# Generated by FakeRAM 2.0
VERSION 5.7 ;
BUSBITCHARS "[]" ;
PROPERTYDEFINITIONS
  MACRO width INTEGER ;
  MACRO depth INTEGER ;
  MACRO banks INTEGER ;
END PROPERTYDEFINITIONS
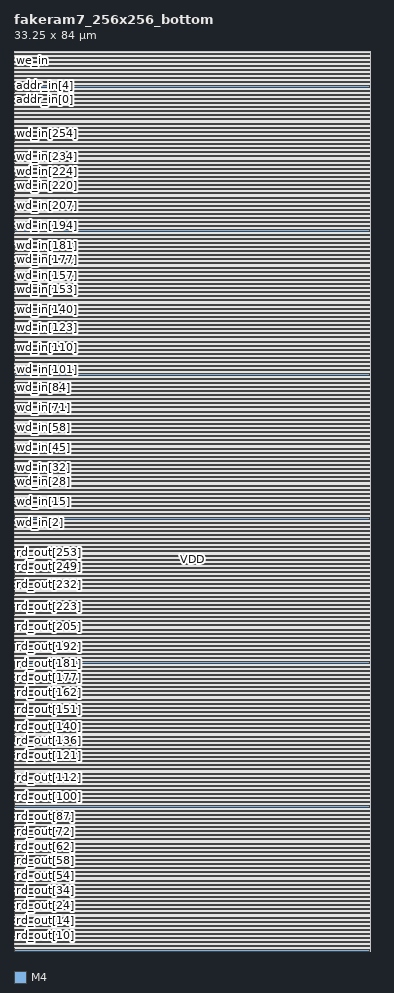
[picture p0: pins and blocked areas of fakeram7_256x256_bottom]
MACRO fakeram7_256x256_bottom
  PROPERTY width 256 ;
  PROPERTY depth 256 ;
  PROPERTY banks 1 ;
  FOREIGN fakeram7_256x256_bottom 0 0 ;
  SYMMETRY X Y R90 ;
  SIZE 33.250 BY 84.000 ;
  CLASS BLOCK ;
  PIN rd_out[0]
    DIRECTION OUTPUT ;
    USE SIGNAL ;
    SHAPE ABUTMENT ;
    PORT
      LAYER M4 ;
      RECT 0.000 0.039 0.024 0.063 ;
    END
  END rd_out[0]
  PIN rd_out[1]
    DIRECTION OUTPUT ;
    USE SIGNAL ;
    SHAPE ABUTMENT ;
    PORT
      LAYER M4 ;
      RECT 0.000 0.183 0.024 0.207 ;
    END
  END rd_out[1]
  PIN rd_out[2]
    DIRECTION OUTPUT ;
    USE SIGNAL ;
    SHAPE ABUTMENT ;
    PORT
      LAYER M4 ;
      RECT 0.000 0.327 0.024 0.351 ;
    END
  END rd_out[2]
  PIN rd_out[3]
    DIRECTION OUTPUT ;
    USE SIGNAL ;
    SHAPE ABUTMENT ;
    PORT
      LAYER M4 ;
      RECT 0.000 0.471 0.024 0.495 ;
    END
  END rd_out[3]
  PIN rd_out[4]
    DIRECTION OUTPUT ;
    USE SIGNAL ;
    SHAPE ABUTMENT ;
    PORT
      LAYER M4 ;
      RECT 0.000 0.615 0.024 0.639 ;
    END
  END rd_out[4]
  PIN rd_out[5]
    DIRECTION OUTPUT ;
    USE SIGNAL ;
    SHAPE ABUTMENT ;
    PORT
      LAYER M4 ;
      RECT 0.000 0.759 0.024 0.783 ;
    END
  END rd_out[5]
  PIN rd_out[6]
    DIRECTION OUTPUT ;
    USE SIGNAL ;
    SHAPE ABUTMENT ;
    PORT
      LAYER M4 ;
      RECT 0.000 0.903 0.024 0.927 ;
    END
  END rd_out[6]
  PIN rd_out[7]
    DIRECTION OUTPUT ;
    USE SIGNAL ;
    SHAPE ABUTMENT ;
    PORT
      LAYER M4 ;
      RECT 0.000 1.047 0.024 1.071 ;
    END
  END rd_out[7]
  PIN rd_out[8]
    DIRECTION OUTPUT ;
    USE SIGNAL ;
    SHAPE ABUTMENT ;
    PORT
      LAYER M4 ;
      RECT 0.000 1.191 0.024 1.215 ;
    END
  END rd_out[8]
  PIN rd_out[9]
    DIRECTION OUTPUT ;
    USE SIGNAL ;
    SHAPE ABUTMENT ;
    PORT
      LAYER M4 ;
      RECT 0.000 1.335 0.024 1.359 ;
    END
  END rd_out[9]
  PIN rd_out[10]
    DIRECTION OUTPUT ;
    USE SIGNAL ;
    SHAPE ABUTMENT ;
    PORT
      LAYER M4 ;
      RECT 0.000 1.479 0.024 1.503 ;
    END
  END rd_out[10]
  PIN rd_out[11]
    DIRECTION OUTPUT ;
    USE SIGNAL ;
    SHAPE ABUTMENT ;
    PORT
      LAYER M4 ;
      RECT 0.000 1.623 0.024 1.647 ;
    END
  END rd_out[11]
  PIN rd_out[12]
    DIRECTION OUTPUT ;
    USE SIGNAL ;
    SHAPE ABUTMENT ;
    PORT
      LAYER M4 ;
      RECT 0.000 1.767 0.024 1.791 ;
    END
  END rd_out[12]
  PIN rd_out[13]
    DIRECTION OUTPUT ;
    USE SIGNAL ;
    SHAPE ABUTMENT ;
    PORT
      LAYER M4 ;
      RECT 0.000 1.911 0.024 1.935 ;
    END
  END rd_out[13]
  PIN rd_out[14]
    DIRECTION OUTPUT ;
    USE SIGNAL ;
    SHAPE ABUTMENT ;
    PORT
      LAYER M4 ;
      RECT 0.000 2.055 0.024 2.079 ;
    END
  END rd_out[14]
  PIN rd_out[15]
    DIRECTION OUTPUT ;
    USE SIGNAL ;
    SHAPE ABUTMENT ;
    PORT
      LAYER M4 ;
      RECT 0.000 2.199 0.024 2.223 ;
    END
  END rd_out[15]
  PIN rd_out[16]
    DIRECTION OUTPUT ;
    USE SIGNAL ;
    SHAPE ABUTMENT ;
    PORT
      LAYER M4 ;
      RECT 0.000 2.343 0.024 2.367 ;
    END
  END rd_out[16]
  PIN rd_out[17]
    DIRECTION OUTPUT ;
    USE SIGNAL ;
    SHAPE ABUTMENT ;
    PORT
      LAYER M4 ;
      RECT 0.000 2.487 0.024 2.511 ;
    END
  END rd_out[17]
  PIN rd_out[18]
    DIRECTION OUTPUT ;
    USE SIGNAL ;
    SHAPE ABUTMENT ;
    PORT
      LAYER M4 ;
      RECT 0.000 2.631 0.024 2.655 ;
    END
  END rd_out[18]
  PIN rd_out[19]
    DIRECTION OUTPUT ;
    USE SIGNAL ;
    SHAPE ABUTMENT ;
    PORT
      LAYER M4 ;
      RECT 0.000 2.775 0.024 2.799 ;
    END
  END rd_out[19]
  PIN rd_out[20]
    DIRECTION OUTPUT ;
    USE SIGNAL ;
    SHAPE ABUTMENT ;
    PORT
      LAYER M4 ;
      RECT 0.000 2.919 0.024 2.943 ;
    END
  END rd_out[20]
  PIN rd_out[21]
    DIRECTION OUTPUT ;
    USE SIGNAL ;
    SHAPE ABUTMENT ;
    PORT
      LAYER M4 ;
      RECT 0.000 3.063 0.024 3.087 ;
    END
  END rd_out[21]
  PIN rd_out[22]
    DIRECTION OUTPUT ;
    USE SIGNAL ;
    SHAPE ABUTMENT ;
    PORT
      LAYER M4 ;
      RECT 0.000 3.207 0.024 3.231 ;
    END
  END rd_out[22]
  PIN rd_out[23]
    DIRECTION OUTPUT ;
    USE SIGNAL ;
    SHAPE ABUTMENT ;
    PORT
      LAYER M4 ;
      RECT 0.000 3.351 0.024 3.375 ;
    END
  END rd_out[23]
  PIN rd_out[24]
    DIRECTION OUTPUT ;
    USE SIGNAL ;
    SHAPE ABUTMENT ;
    PORT
      LAYER M4 ;
      RECT 0.000 3.495 0.024 3.519 ;
    END
  END rd_out[24]
  PIN rd_out[25]
    DIRECTION OUTPUT ;
    USE SIGNAL ;
    SHAPE ABUTMENT ;
    PORT
      LAYER M4 ;
      RECT 0.000 3.639 0.024 3.663 ;
    END
  END rd_out[25]
  PIN rd_out[26]
    DIRECTION OUTPUT ;
    USE SIGNAL ;
    SHAPE ABUTMENT ;
    PORT
      LAYER M4 ;
      RECT 0.000 3.783 0.024 3.807 ;
    END
  END rd_out[26]
  PIN rd_out[27]
    DIRECTION OUTPUT ;
    USE SIGNAL ;
    SHAPE ABUTMENT ;
    PORT
      LAYER M4 ;
      RECT 0.000 3.927 0.024 3.951 ;
    END
  END rd_out[27]
  PIN rd_out[28]
    DIRECTION OUTPUT ;
    USE SIGNAL ;
    SHAPE ABUTMENT ;
    PORT
      LAYER M4 ;
      RECT 0.000 4.071 0.024 4.095 ;
    END
  END rd_out[28]
  PIN rd_out[29]
    DIRECTION OUTPUT ;
    USE SIGNAL ;
    SHAPE ABUTMENT ;
    PORT
      LAYER M4 ;
      RECT 0.000 4.215 0.024 4.239 ;
    END
  END rd_out[29]
  PIN rd_out[30]
    DIRECTION OUTPUT ;
    USE SIGNAL ;
    SHAPE ABUTMENT ;
    PORT
      LAYER M4 ;
      RECT 0.000 4.359 0.024 4.383 ;
    END
  END rd_out[30]
  PIN rd_out[31]
    DIRECTION OUTPUT ;
    USE SIGNAL ;
    SHAPE ABUTMENT ;
    PORT
      LAYER M4 ;
      RECT 0.000 4.503 0.024 4.527 ;
    END
  END rd_out[31]
  PIN rd_out[32]
    DIRECTION OUTPUT ;
    USE SIGNAL ;
    SHAPE ABUTMENT ;
    PORT
      LAYER M4 ;
      RECT 0.000 4.647 0.024 4.671 ;
    END
  END rd_out[32]
  PIN rd_out[33]
    DIRECTION OUTPUT ;
    USE SIGNAL ;
    SHAPE ABUTMENT ;
    PORT
      LAYER M4 ;
      RECT 0.000 4.791 0.024 4.815 ;
    END
  END rd_out[33]
  PIN rd_out[34]
    DIRECTION OUTPUT ;
    USE SIGNAL ;
    SHAPE ABUTMENT ;
    PORT
      LAYER M4 ;
      RECT 0.000 4.935 0.024 4.959 ;
    END
  END rd_out[34]
  PIN rd_out[35]
    DIRECTION OUTPUT ;
    USE SIGNAL ;
    SHAPE ABUTMENT ;
    PORT
      LAYER M4 ;
      RECT 0.000 5.079 0.024 5.103 ;
    END
  END rd_out[35]
  PIN rd_out[36]
    DIRECTION OUTPUT ;
    USE SIGNAL ;
    SHAPE ABUTMENT ;
    PORT
      LAYER M4 ;
      RECT 0.000 5.223 0.024 5.247 ;
    END
  END rd_out[36]
  PIN rd_out[37]
    DIRECTION OUTPUT ;
    USE SIGNAL ;
    SHAPE ABUTMENT ;
    PORT
      LAYER M4 ;
      RECT 0.000 5.367 0.024 5.391 ;
    END
  END rd_out[37]
  PIN rd_out[38]
    DIRECTION OUTPUT ;
    USE SIGNAL ;
    SHAPE ABUTMENT ;
    PORT
      LAYER M4 ;
      RECT 0.000 5.511 0.024 5.535 ;
    END
  END rd_out[38]
  PIN rd_out[39]
    DIRECTION OUTPUT ;
    USE SIGNAL ;
    SHAPE ABUTMENT ;
    PORT
      LAYER M4 ;
      RECT 0.000 5.655 0.024 5.679 ;
    END
  END rd_out[39]
  PIN rd_out[40]
    DIRECTION OUTPUT ;
    USE SIGNAL ;
    SHAPE ABUTMENT ;
    PORT
      LAYER M4 ;
      RECT 0.000 5.799 0.024 5.823 ;
    END
  END rd_out[40]
  PIN rd_out[41]
    DIRECTION OUTPUT ;
    USE SIGNAL ;
    SHAPE ABUTMENT ;
    PORT
      LAYER M4 ;
      RECT 0.000 5.943 0.024 5.967 ;
    END
  END rd_out[41]
  PIN rd_out[42]
    DIRECTION OUTPUT ;
    USE SIGNAL ;
    SHAPE ABUTMENT ;
    PORT
      LAYER M4 ;
      RECT 0.000 6.087 0.024 6.111 ;
    END
  END rd_out[42]
  PIN rd_out[43]
    DIRECTION OUTPUT ;
    USE SIGNAL ;
    SHAPE ABUTMENT ;
    PORT
      LAYER M4 ;
      RECT 0.000 6.231 0.024 6.255 ;
    END
  END rd_out[43]
  PIN rd_out[44]
    DIRECTION OUTPUT ;
    USE SIGNAL ;
    SHAPE ABUTMENT ;
    PORT
      LAYER M4 ;
      RECT 0.000 6.375 0.024 6.399 ;
    END
  END rd_out[44]
  PIN rd_out[45]
    DIRECTION OUTPUT ;
    USE SIGNAL ;
    SHAPE ABUTMENT ;
    PORT
      LAYER M4 ;
      RECT 0.000 6.519 0.024 6.543 ;
    END
  END rd_out[45]
  PIN rd_out[46]
    DIRECTION OUTPUT ;
    USE SIGNAL ;
    SHAPE ABUTMENT ;
    PORT
      LAYER M4 ;
      RECT 0.000 6.663 0.024 6.687 ;
    END
  END rd_out[46]
  PIN rd_out[47]
    DIRECTION OUTPUT ;
    USE SIGNAL ;
    SHAPE ABUTMENT ;
    PORT
      LAYER M4 ;
      RECT 0.000 6.807 0.024 6.831 ;
    END
  END rd_out[47]
  PIN rd_out[48]
    DIRECTION OUTPUT ;
    USE SIGNAL ;
    SHAPE ABUTMENT ;
    PORT
      LAYER M4 ;
      RECT 0.000 6.951 0.024 6.975 ;
    END
  END rd_out[48]
  PIN rd_out[49]
    DIRECTION OUTPUT ;
    USE SIGNAL ;
    SHAPE ABUTMENT ;
    PORT
      LAYER M4 ;
      RECT 0.000 7.095 0.024 7.119 ;
    END
  END rd_out[49]
  PIN rd_out[50]
    DIRECTION OUTPUT ;
    USE SIGNAL ;
    SHAPE ABUTMENT ;
    PORT
      LAYER M4 ;
      RECT 0.000 7.239 0.024 7.263 ;
    END
  END rd_out[50]
  PIN rd_out[51]
    DIRECTION OUTPUT ;
    USE SIGNAL ;
    SHAPE ABUTMENT ;
    PORT
      LAYER M4 ;
      RECT 0.000 7.383 0.024 7.407 ;
    END
  END rd_out[51]
  PIN rd_out[52]
    DIRECTION OUTPUT ;
    USE SIGNAL ;
    SHAPE ABUTMENT ;
    PORT
      LAYER M4 ;
      RECT 0.000 7.527 0.024 7.551 ;
    END
  END rd_out[52]
  PIN rd_out[53]
    DIRECTION OUTPUT ;
    USE SIGNAL ;
    SHAPE ABUTMENT ;
    PORT
      LAYER M4 ;
      RECT 0.000 7.671 0.024 7.695 ;
    END
  END rd_out[53]
  PIN rd_out[54]
    DIRECTION OUTPUT ;
    USE SIGNAL ;
    SHAPE ABUTMENT ;
    PORT
      LAYER M4 ;
      RECT 0.000 7.815 0.024 7.839 ;
    END
  END rd_out[54]
  PIN rd_out[55]
    DIRECTION OUTPUT ;
    USE SIGNAL ;
    SHAPE ABUTMENT ;
    PORT
      LAYER M4 ;
      RECT 0.000 7.959 0.024 7.983 ;
    END
  END rd_out[55]
  PIN rd_out[56]
    DIRECTION OUTPUT ;
    USE SIGNAL ;
    SHAPE ABUTMENT ;
    PORT
      LAYER M4 ;
      RECT 0.000 8.103 0.024 8.127 ;
    END
  END rd_out[56]
  PIN rd_out[57]
    DIRECTION OUTPUT ;
    USE SIGNAL ;
    SHAPE ABUTMENT ;
    PORT
      LAYER M4 ;
      RECT 0.000 8.247 0.024 8.271 ;
    END
  END rd_out[57]
  PIN rd_out[58]
    DIRECTION OUTPUT ;
    USE SIGNAL ;
    SHAPE ABUTMENT ;
    PORT
      LAYER M4 ;
      RECT 0.000 8.391 0.024 8.415 ;
    END
  END rd_out[58]
  PIN rd_out[59]
    DIRECTION OUTPUT ;
    USE SIGNAL ;
    SHAPE ABUTMENT ;
    PORT
      LAYER M4 ;
      RECT 0.000 8.535 0.024 8.559 ;
    END
  END rd_out[59]
  PIN rd_out[60]
    DIRECTION OUTPUT ;
    USE SIGNAL ;
    SHAPE ABUTMENT ;
    PORT
      LAYER M4 ;
      RECT 0.000 8.679 0.024 8.703 ;
    END
  END rd_out[60]
  PIN rd_out[61]
    DIRECTION OUTPUT ;
    USE SIGNAL ;
    SHAPE ABUTMENT ;
    PORT
      LAYER M4 ;
      RECT 0.000 8.823 0.024 8.847 ;
    END
  END rd_out[61]
  PIN rd_out[62]
    DIRECTION OUTPUT ;
    USE SIGNAL ;
    SHAPE ABUTMENT ;
    PORT
      LAYER M4 ;
      RECT 0.000 8.967 0.024 8.991 ;
    END
  END rd_out[62]
  PIN rd_out[63]
    DIRECTION OUTPUT ;
    USE SIGNAL ;
    SHAPE ABUTMENT ;
    PORT
      LAYER M4 ;
      RECT 0.000 9.111 0.024 9.135 ;
    END
  END rd_out[63]
  PIN rd_out[64]
    DIRECTION OUTPUT ;
    USE SIGNAL ;
    SHAPE ABUTMENT ;
    PORT
      LAYER M4 ;
      RECT 0.000 9.255 0.024 9.279 ;
    END
  END rd_out[64]
  PIN rd_out[65]
    DIRECTION OUTPUT ;
    USE SIGNAL ;
    SHAPE ABUTMENT ;
    PORT
      LAYER M4 ;
      RECT 0.000 9.399 0.024 9.423 ;
    END
  END rd_out[65]
  PIN rd_out[66]
    DIRECTION OUTPUT ;
    USE SIGNAL ;
    SHAPE ABUTMENT ;
    PORT
      LAYER M4 ;
      RECT 0.000 9.543 0.024 9.567 ;
    END
  END rd_out[66]
  PIN rd_out[67]
    DIRECTION OUTPUT ;
    USE SIGNAL ;
    SHAPE ABUTMENT ;
    PORT
      LAYER M4 ;
      RECT 0.000 9.687 0.024 9.711 ;
    END
  END rd_out[67]
  PIN rd_out[68]
    DIRECTION OUTPUT ;
    USE SIGNAL ;
    SHAPE ABUTMENT ;
    PORT
      LAYER M4 ;
      RECT 0.000 9.831 0.024 9.855 ;
    END
  END rd_out[68]
  PIN rd_out[69]
    DIRECTION OUTPUT ;
    USE SIGNAL ;
    SHAPE ABUTMENT ;
    PORT
      LAYER M4 ;
      RECT 0.000 9.975 0.024 9.999 ;
    END
  END rd_out[69]
  PIN rd_out[70]
    DIRECTION OUTPUT ;
    USE SIGNAL ;
    SHAPE ABUTMENT ;
    PORT
      LAYER M4 ;
      RECT 0.000 10.119 0.024 10.143 ;
    END
  END rd_out[70]
  PIN rd_out[71]
    DIRECTION OUTPUT ;
    USE SIGNAL ;
    SHAPE ABUTMENT ;
    PORT
      LAYER M4 ;
      RECT 0.000 10.263 0.024 10.287 ;
    END
  END rd_out[71]
  PIN rd_out[72]
    DIRECTION OUTPUT ;
    USE SIGNAL ;
    SHAPE ABUTMENT ;
    PORT
      LAYER M4 ;
      RECT 0.000 10.407 0.024 10.431 ;
    END
  END rd_out[72]
  PIN rd_out[73]
    DIRECTION OUTPUT ;
    USE SIGNAL ;
    SHAPE ABUTMENT ;
    PORT
      LAYER M4 ;
      RECT 0.000 10.551 0.024 10.575 ;
    END
  END rd_out[73]
  PIN rd_out[74]
    DIRECTION OUTPUT ;
    USE SIGNAL ;
    SHAPE ABUTMENT ;
    PORT
      LAYER M4 ;
      RECT 0.000 10.695 0.024 10.719 ;
    END
  END rd_out[74]
  PIN rd_out[75]
    DIRECTION OUTPUT ;
    USE SIGNAL ;
    SHAPE ABUTMENT ;
    PORT
      LAYER M4 ;
      RECT 0.000 10.839 0.024 10.863 ;
    END
  END rd_out[75]
  PIN rd_out[76]
    DIRECTION OUTPUT ;
    USE SIGNAL ;
    SHAPE ABUTMENT ;
    PORT
      LAYER M4 ;
      RECT 0.000 10.983 0.024 11.007 ;
    END
  END rd_out[76]
  PIN rd_out[77]
    DIRECTION OUTPUT ;
    USE SIGNAL ;
    SHAPE ABUTMENT ;
    PORT
      LAYER M4 ;
      RECT 0.000 11.127 0.024 11.151 ;
    END
  END rd_out[77]
  PIN rd_out[78]
    DIRECTION OUTPUT ;
    USE SIGNAL ;
    SHAPE ABUTMENT ;
    PORT
      LAYER M4 ;
      RECT 0.000 11.271 0.024 11.295 ;
    END
  END rd_out[78]
  PIN rd_out[79]
    DIRECTION OUTPUT ;
    USE SIGNAL ;
    SHAPE ABUTMENT ;
    PORT
      LAYER M4 ;
      RECT 0.000 11.415 0.024 11.439 ;
    END
  END rd_out[79]
  PIN rd_out[80]
    DIRECTION OUTPUT ;
    USE SIGNAL ;
    SHAPE ABUTMENT ;
    PORT
      LAYER M4 ;
      RECT 0.000 11.559 0.024 11.583 ;
    END
  END rd_out[80]
  PIN rd_out[81]
    DIRECTION OUTPUT ;
    USE SIGNAL ;
    SHAPE ABUTMENT ;
    PORT
      LAYER M4 ;
      RECT 0.000 11.703 0.024 11.727 ;
    END
  END rd_out[81]
  PIN rd_out[82]
    DIRECTION OUTPUT ;
    USE SIGNAL ;
    SHAPE ABUTMENT ;
    PORT
      LAYER M4 ;
      RECT 0.000 11.847 0.024 11.871 ;
    END
  END rd_out[82]
  PIN rd_out[83]
    DIRECTION OUTPUT ;
    USE SIGNAL ;
    SHAPE ABUTMENT ;
    PORT
      LAYER M4 ;
      RECT 0.000 11.991 0.024 12.015 ;
    END
  END rd_out[83]
  PIN rd_out[84]
    DIRECTION OUTPUT ;
    USE SIGNAL ;
    SHAPE ABUTMENT ;
    PORT
      LAYER M4 ;
      RECT 0.000 12.135 0.024 12.159 ;
    END
  END rd_out[84]
  PIN rd_out[85]
    DIRECTION OUTPUT ;
    USE SIGNAL ;
    SHAPE ABUTMENT ;
    PORT
      LAYER M4 ;
      RECT 0.000 12.279 0.024 12.303 ;
    END
  END rd_out[85]
  PIN rd_out[86]
    DIRECTION OUTPUT ;
    USE SIGNAL ;
    SHAPE ABUTMENT ;
    PORT
      LAYER M4 ;
      RECT 0.000 12.423 0.024 12.447 ;
    END
  END rd_out[86]
  PIN rd_out[87]
    DIRECTION OUTPUT ;
    USE SIGNAL ;
    SHAPE ABUTMENT ;
    PORT
      LAYER M4 ;
      RECT 0.000 12.567 0.024 12.591 ;
    END
  END rd_out[87]
  PIN rd_out[88]
    DIRECTION OUTPUT ;
    USE SIGNAL ;
    SHAPE ABUTMENT ;
    PORT
      LAYER M4 ;
      RECT 0.000 12.711 0.024 12.735 ;
    END
  END rd_out[88]
  PIN rd_out[89]
    DIRECTION OUTPUT ;
    USE SIGNAL ;
    SHAPE ABUTMENT ;
    PORT
      LAYER M4 ;
      RECT 0.000 12.855 0.024 12.879 ;
    END
  END rd_out[89]
  PIN rd_out[90]
    DIRECTION OUTPUT ;
    USE SIGNAL ;
    SHAPE ABUTMENT ;
    PORT
      LAYER M4 ;
      RECT 0.000 12.999 0.024 13.023 ;
    END
  END rd_out[90]
  PIN rd_out[91]
    DIRECTION OUTPUT ;
    USE SIGNAL ;
    SHAPE ABUTMENT ;
    PORT
      LAYER M4 ;
      RECT 0.000 13.143 0.024 13.167 ;
    END
  END rd_out[91]
  PIN rd_out[92]
    DIRECTION OUTPUT ;
    USE SIGNAL ;
    SHAPE ABUTMENT ;
    PORT
      LAYER M4 ;
      RECT 0.000 13.287 0.024 13.311 ;
    END
  END rd_out[92]
  PIN rd_out[93]
    DIRECTION OUTPUT ;
    USE SIGNAL ;
    SHAPE ABUTMENT ;
    PORT
      LAYER M4 ;
      RECT 0.000 13.431 0.024 13.455 ;
    END
  END rd_out[93]
  PIN rd_out[94]
    DIRECTION OUTPUT ;
    USE SIGNAL ;
    SHAPE ABUTMENT ;
    PORT
      LAYER M4 ;
      RECT 0.000 13.575 0.024 13.599 ;
    END
  END rd_out[94]
  PIN rd_out[95]
    DIRECTION OUTPUT ;
    USE SIGNAL ;
    SHAPE ABUTMENT ;
    PORT
      LAYER M4 ;
      RECT 0.000 13.719 0.024 13.743 ;
    END
  END rd_out[95]
  PIN rd_out[96]
    DIRECTION OUTPUT ;
    USE SIGNAL ;
    SHAPE ABUTMENT ;
    PORT
      LAYER M4 ;
      RECT 0.000 13.863 0.024 13.887 ;
    END
  END rd_out[96]
  PIN rd_out[97]
    DIRECTION OUTPUT ;
    USE SIGNAL ;
    SHAPE ABUTMENT ;
    PORT
      LAYER M4 ;
      RECT 0.000 14.007 0.024 14.031 ;
    END
  END rd_out[97]
  PIN rd_out[98]
    DIRECTION OUTPUT ;
    USE SIGNAL ;
    SHAPE ABUTMENT ;
    PORT
      LAYER M4 ;
      RECT 0.000 14.151 0.024 14.175 ;
    END
  END rd_out[98]
  PIN rd_out[99]
    DIRECTION OUTPUT ;
    USE SIGNAL ;
    SHAPE ABUTMENT ;
    PORT
      LAYER M4 ;
      RECT 0.000 14.295 0.024 14.319 ;
    END
  END rd_out[99]
  PIN rd_out[100]
    DIRECTION OUTPUT ;
    USE SIGNAL ;
    SHAPE ABUTMENT ;
    PORT
      LAYER M4 ;
      RECT 0.000 14.439 0.024 14.463 ;
    END
  END rd_out[100]
  PIN rd_out[101]
    DIRECTION OUTPUT ;
    USE SIGNAL ;
    SHAPE ABUTMENT ;
    PORT
      LAYER M4 ;
      RECT 0.000 14.583 0.024 14.607 ;
    END
  END rd_out[101]
  PIN rd_out[102]
    DIRECTION OUTPUT ;
    USE SIGNAL ;
    SHAPE ABUTMENT ;
    PORT
      LAYER M4 ;
      RECT 0.000 14.727 0.024 14.751 ;
    END
  END rd_out[102]
  PIN rd_out[103]
    DIRECTION OUTPUT ;
    USE SIGNAL ;
    SHAPE ABUTMENT ;
    PORT
      LAYER M4 ;
      RECT 0.000 14.871 0.024 14.895 ;
    END
  END rd_out[103]
  PIN rd_out[104]
    DIRECTION OUTPUT ;
    USE SIGNAL ;
    SHAPE ABUTMENT ;
    PORT
      LAYER M4 ;
      RECT 0.000 15.015 0.024 15.039 ;
    END
  END rd_out[104]
  PIN rd_out[105]
    DIRECTION OUTPUT ;
    USE SIGNAL ;
    SHAPE ABUTMENT ;
    PORT
      LAYER M4 ;
      RECT 0.000 15.159 0.024 15.183 ;
    END
  END rd_out[105]
  PIN rd_out[106]
    DIRECTION OUTPUT ;
    USE SIGNAL ;
    SHAPE ABUTMENT ;
    PORT
      LAYER M4 ;
      RECT 0.000 15.303 0.024 15.327 ;
    END
  END rd_out[106]
  PIN rd_out[107]
    DIRECTION OUTPUT ;
    USE SIGNAL ;
    SHAPE ABUTMENT ;
    PORT
      LAYER M4 ;
      RECT 0.000 15.447 0.024 15.471 ;
    END
  END rd_out[107]
  PIN rd_out[108]
    DIRECTION OUTPUT ;
    USE SIGNAL ;
    SHAPE ABUTMENT ;
    PORT
      LAYER M4 ;
      RECT 0.000 15.591 0.024 15.615 ;
    END
  END rd_out[108]
  PIN rd_out[109]
    DIRECTION OUTPUT ;
    USE SIGNAL ;
    SHAPE ABUTMENT ;
    PORT
      LAYER M4 ;
      RECT 0.000 15.735 0.024 15.759 ;
    END
  END rd_out[109]
  PIN rd_out[110]
    DIRECTION OUTPUT ;
    USE SIGNAL ;
    SHAPE ABUTMENT ;
    PORT
      LAYER M4 ;
      RECT 0.000 15.879 0.024 15.903 ;
    END
  END rd_out[110]
  PIN rd_out[111]
    DIRECTION OUTPUT ;
    USE SIGNAL ;
    SHAPE ABUTMENT ;
    PORT
      LAYER M4 ;
      RECT 0.000 16.023 0.024 16.047 ;
    END
  END rd_out[111]
  PIN rd_out[112]
    DIRECTION OUTPUT ;
    USE SIGNAL ;
    SHAPE ABUTMENT ;
    PORT
      LAYER M4 ;
      RECT 0.000 16.167 0.024 16.191 ;
    END
  END rd_out[112]
  PIN rd_out[113]
    DIRECTION OUTPUT ;
    USE SIGNAL ;
    SHAPE ABUTMENT ;
    PORT
      LAYER M4 ;
      RECT 0.000 16.311 0.024 16.335 ;
    END
  END rd_out[113]
  PIN rd_out[114]
    DIRECTION OUTPUT ;
    USE SIGNAL ;
    SHAPE ABUTMENT ;
    PORT
      LAYER M4 ;
      RECT 0.000 16.455 0.024 16.479 ;
    END
  END rd_out[114]
  PIN rd_out[115]
    DIRECTION OUTPUT ;
    USE SIGNAL ;
    SHAPE ABUTMENT ;
    PORT
      LAYER M4 ;
      RECT 0.000 16.599 0.024 16.623 ;
    END
  END rd_out[115]
  PIN rd_out[116]
    DIRECTION OUTPUT ;
    USE SIGNAL ;
    SHAPE ABUTMENT ;
    PORT
      LAYER M4 ;
      RECT 0.000 16.743 0.024 16.767 ;
    END
  END rd_out[116]
  PIN rd_out[117]
    DIRECTION OUTPUT ;
    USE SIGNAL ;
    SHAPE ABUTMENT ;
    PORT
      LAYER M4 ;
      RECT 0.000 16.887 0.024 16.911 ;
    END
  END rd_out[117]
  PIN rd_out[118]
    DIRECTION OUTPUT ;
    USE SIGNAL ;
    SHAPE ABUTMENT ;
    PORT
      LAYER M4 ;
      RECT 0.000 17.031 0.024 17.055 ;
    END
  END rd_out[118]
  PIN rd_out[119]
    DIRECTION OUTPUT ;
    USE SIGNAL ;
    SHAPE ABUTMENT ;
    PORT
      LAYER M4 ;
      RECT 0.000 17.175 0.024 17.199 ;
    END
  END rd_out[119]
  PIN rd_out[120]
    DIRECTION OUTPUT ;
    USE SIGNAL ;
    SHAPE ABUTMENT ;
    PORT
      LAYER M4 ;
      RECT 0.000 17.319 0.024 17.343 ;
    END
  END rd_out[120]
  PIN rd_out[121]
    DIRECTION OUTPUT ;
    USE SIGNAL ;
    SHAPE ABUTMENT ;
    PORT
      LAYER M4 ;
      RECT 0.000 17.463 0.024 17.487 ;
    END
  END rd_out[121]
  PIN rd_out[122]
    DIRECTION OUTPUT ;
    USE SIGNAL ;
    SHAPE ABUTMENT ;
    PORT
      LAYER M4 ;
      RECT 0.000 17.607 0.024 17.631 ;
    END
  END rd_out[122]
  PIN rd_out[123]
    DIRECTION OUTPUT ;
    USE SIGNAL ;
    SHAPE ABUTMENT ;
    PORT
      LAYER M4 ;
      RECT 0.000 17.751 0.024 17.775 ;
    END
  END rd_out[123]
  PIN rd_out[124]
    DIRECTION OUTPUT ;
    USE SIGNAL ;
    SHAPE ABUTMENT ;
    PORT
      LAYER M4 ;
      RECT 0.000 17.895 0.024 17.919 ;
    END
  END rd_out[124]
  PIN rd_out[125]
    DIRECTION OUTPUT ;
    USE SIGNAL ;
    SHAPE ABUTMENT ;
    PORT
      LAYER M4 ;
      RECT 0.000 18.039 0.024 18.063 ;
    END
  END rd_out[125]
  PIN rd_out[126]
    DIRECTION OUTPUT ;
    USE SIGNAL ;
    SHAPE ABUTMENT ;
    PORT
      LAYER M4 ;
      RECT 0.000 18.183 0.024 18.207 ;
    END
  END rd_out[126]
  PIN rd_out[127]
    DIRECTION OUTPUT ;
    USE SIGNAL ;
    SHAPE ABUTMENT ;
    PORT
      LAYER M4 ;
      RECT 0.000 18.327 0.024 18.351 ;
    END
  END rd_out[127]
  PIN rd_out[128]
    DIRECTION OUTPUT ;
    USE SIGNAL ;
    SHAPE ABUTMENT ;
    PORT
      LAYER M4 ;
      RECT 0.000 18.471 0.024 18.495 ;
    END
  END rd_out[128]
  PIN rd_out[129]
    DIRECTION OUTPUT ;
    USE SIGNAL ;
    SHAPE ABUTMENT ;
    PORT
      LAYER M4 ;
      RECT 0.000 18.615 0.024 18.639 ;
    END
  END rd_out[129]
  PIN rd_out[130]
    DIRECTION OUTPUT ;
    USE SIGNAL ;
    SHAPE ABUTMENT ;
    PORT
      LAYER M4 ;
      RECT 0.000 18.759 0.024 18.783 ;
    END
  END rd_out[130]
  PIN rd_out[131]
    DIRECTION OUTPUT ;
    USE SIGNAL ;
    SHAPE ABUTMENT ;
    PORT
      LAYER M4 ;
      RECT 0.000 18.903 0.024 18.927 ;
    END
  END rd_out[131]
  PIN rd_out[132]
    DIRECTION OUTPUT ;
    USE SIGNAL ;
    SHAPE ABUTMENT ;
    PORT
      LAYER M4 ;
      RECT 0.000 19.047 0.024 19.071 ;
    END
  END rd_out[132]
  PIN rd_out[133]
    DIRECTION OUTPUT ;
    USE SIGNAL ;
    SHAPE ABUTMENT ;
    PORT
      LAYER M4 ;
      RECT 0.000 19.191 0.024 19.215 ;
    END
  END rd_out[133]
  PIN rd_out[134]
    DIRECTION OUTPUT ;
    USE SIGNAL ;
    SHAPE ABUTMENT ;
    PORT
      LAYER M4 ;
      RECT 0.000 19.335 0.024 19.359 ;
    END
  END rd_out[134]
  PIN rd_out[135]
    DIRECTION OUTPUT ;
    USE SIGNAL ;
    SHAPE ABUTMENT ;
    PORT
      LAYER M4 ;
      RECT 0.000 19.479 0.024 19.503 ;
    END
  END rd_out[135]
  PIN rd_out[136]
    DIRECTION OUTPUT ;
    USE SIGNAL ;
    SHAPE ABUTMENT ;
    PORT
      LAYER M4 ;
      RECT 0.000 19.623 0.024 19.647 ;
    END
  END rd_out[136]
  PIN rd_out[137]
    DIRECTION OUTPUT ;
    USE SIGNAL ;
    SHAPE ABUTMENT ;
    PORT
      LAYER M4 ;
      RECT 0.000 19.767 0.024 19.791 ;
    END
  END rd_out[137]
  PIN rd_out[138]
    DIRECTION OUTPUT ;
    USE SIGNAL ;
    SHAPE ABUTMENT ;
    PORT
      LAYER M4 ;
      RECT 0.000 19.911 0.024 19.935 ;
    END
  END rd_out[138]
  PIN rd_out[139]
    DIRECTION OUTPUT ;
    USE SIGNAL ;
    SHAPE ABUTMENT ;
    PORT
      LAYER M4 ;
      RECT 0.000 20.055 0.024 20.079 ;
    END
  END rd_out[139]
  PIN rd_out[140]
    DIRECTION OUTPUT ;
    USE SIGNAL ;
    SHAPE ABUTMENT ;
    PORT
      LAYER M4 ;
      RECT 0.000 20.199 0.024 20.223 ;
    END
  END rd_out[140]
  PIN rd_out[141]
    DIRECTION OUTPUT ;
    USE SIGNAL ;
    SHAPE ABUTMENT ;
    PORT
      LAYER M4 ;
      RECT 0.000 20.343 0.024 20.367 ;
    END
  END rd_out[141]
  PIN rd_out[142]
    DIRECTION OUTPUT ;
    USE SIGNAL ;
    SHAPE ABUTMENT ;
    PORT
      LAYER M4 ;
      RECT 0.000 20.487 0.024 20.511 ;
    END
  END rd_out[142]
  PIN rd_out[143]
    DIRECTION OUTPUT ;
    USE SIGNAL ;
    SHAPE ABUTMENT ;
    PORT
      LAYER M4 ;
      RECT 0.000 20.631 0.024 20.655 ;
    END
  END rd_out[143]
  PIN rd_out[144]
    DIRECTION OUTPUT ;
    USE SIGNAL ;
    SHAPE ABUTMENT ;
    PORT
      LAYER M4 ;
      RECT 0.000 20.775 0.024 20.799 ;
    END
  END rd_out[144]
  PIN rd_out[145]
    DIRECTION OUTPUT ;
    USE SIGNAL ;
    SHAPE ABUTMENT ;
    PORT
      LAYER M4 ;
      RECT 0.000 20.919 0.024 20.943 ;
    END
  END rd_out[145]
  PIN rd_out[146]
    DIRECTION OUTPUT ;
    USE SIGNAL ;
    SHAPE ABUTMENT ;
    PORT
      LAYER M4 ;
      RECT 0.000 21.063 0.024 21.087 ;
    END
  END rd_out[146]
  PIN rd_out[147]
    DIRECTION OUTPUT ;
    USE SIGNAL ;
    SHAPE ABUTMENT ;
    PORT
      LAYER M4 ;
      RECT 0.000 21.207 0.024 21.231 ;
    END
  END rd_out[147]
  PIN rd_out[148]
    DIRECTION OUTPUT ;
    USE SIGNAL ;
    SHAPE ABUTMENT ;
    PORT
      LAYER M4 ;
      RECT 0.000 21.351 0.024 21.375 ;
    END
  END rd_out[148]
  PIN rd_out[149]
    DIRECTION OUTPUT ;
    USE SIGNAL ;
    SHAPE ABUTMENT ;
    PORT
      LAYER M4 ;
      RECT 0.000 21.495 0.024 21.519 ;
    END
  END rd_out[149]
  PIN rd_out[150]
    DIRECTION OUTPUT ;
    USE SIGNAL ;
    SHAPE ABUTMENT ;
    PORT
      LAYER M4 ;
      RECT 0.000 21.639 0.024 21.663 ;
    END
  END rd_out[150]
  PIN rd_out[151]
    DIRECTION OUTPUT ;
    USE SIGNAL ;
    SHAPE ABUTMENT ;
    PORT
      LAYER M4 ;
      RECT 0.000 21.783 0.024 21.807 ;
    END
  END rd_out[151]
  PIN rd_out[152]
    DIRECTION OUTPUT ;
    USE SIGNAL ;
    SHAPE ABUTMENT ;
    PORT
      LAYER M4 ;
      RECT 0.000 21.927 0.024 21.951 ;
    END
  END rd_out[152]
  PIN rd_out[153]
    DIRECTION OUTPUT ;
    USE SIGNAL ;
    SHAPE ABUTMENT ;
    PORT
      LAYER M4 ;
      RECT 0.000 22.071 0.024 22.095 ;
    END
  END rd_out[153]
  PIN rd_out[154]
    DIRECTION OUTPUT ;
    USE SIGNAL ;
    SHAPE ABUTMENT ;
    PORT
      LAYER M4 ;
      RECT 0.000 22.215 0.024 22.239 ;
    END
  END rd_out[154]
  PIN rd_out[155]
    DIRECTION OUTPUT ;
    USE SIGNAL ;
    SHAPE ABUTMENT ;
    PORT
      LAYER M4 ;
      RECT 0.000 22.359 0.024 22.383 ;
    END
  END rd_out[155]
  PIN rd_out[156]
    DIRECTION OUTPUT ;
    USE SIGNAL ;
    SHAPE ABUTMENT ;
    PORT
      LAYER M4 ;
      RECT 0.000 22.503 0.024 22.527 ;
    END
  END rd_out[156]
  PIN rd_out[157]
    DIRECTION OUTPUT ;
    USE SIGNAL ;
    SHAPE ABUTMENT ;
    PORT
      LAYER M4 ;
      RECT 0.000 22.647 0.024 22.671 ;
    END
  END rd_out[157]
  PIN rd_out[158]
    DIRECTION OUTPUT ;
    USE SIGNAL ;
    SHAPE ABUTMENT ;
    PORT
      LAYER M4 ;
      RECT 0.000 22.791 0.024 22.815 ;
    END
  END rd_out[158]
  PIN rd_out[159]
    DIRECTION OUTPUT ;
    USE SIGNAL ;
    SHAPE ABUTMENT ;
    PORT
      LAYER M4 ;
      RECT 0.000 22.935 0.024 22.959 ;
    END
  END rd_out[159]
  PIN rd_out[160]
    DIRECTION OUTPUT ;
    USE SIGNAL ;
    SHAPE ABUTMENT ;
    PORT
      LAYER M4 ;
      RECT 0.000 23.079 0.024 23.103 ;
    END
  END rd_out[160]
  PIN rd_out[161]
    DIRECTION OUTPUT ;
    USE SIGNAL ;
    SHAPE ABUTMENT ;
    PORT
      LAYER M4 ;
      RECT 0.000 23.223 0.024 23.247 ;
    END
  END rd_out[161]
  PIN rd_out[162]
    DIRECTION OUTPUT ;
    USE SIGNAL ;
    SHAPE ABUTMENT ;
    PORT
      LAYER M4 ;
      RECT 0.000 23.367 0.024 23.391 ;
    END
  END rd_out[162]
  PIN rd_out[163]
    DIRECTION OUTPUT ;
    USE SIGNAL ;
    SHAPE ABUTMENT ;
    PORT
      LAYER M4 ;
      RECT 0.000 23.511 0.024 23.535 ;
    END
  END rd_out[163]
  PIN rd_out[164]
    DIRECTION OUTPUT ;
    USE SIGNAL ;
    SHAPE ABUTMENT ;
    PORT
      LAYER M4 ;
      RECT 0.000 23.655 0.024 23.679 ;
    END
  END rd_out[164]
  PIN rd_out[165]
    DIRECTION OUTPUT ;
    USE SIGNAL ;
    SHAPE ABUTMENT ;
    PORT
      LAYER M4 ;
      RECT 0.000 23.799 0.024 23.823 ;
    END
  END rd_out[165]
  PIN rd_out[166]
    DIRECTION OUTPUT ;
    USE SIGNAL ;
    SHAPE ABUTMENT ;
    PORT
      LAYER M4 ;
      RECT 0.000 23.943 0.024 23.967 ;
    END
  END rd_out[166]
  PIN rd_out[167]
    DIRECTION OUTPUT ;
    USE SIGNAL ;
    SHAPE ABUTMENT ;
    PORT
      LAYER M4 ;
      RECT 0.000 24.087 0.024 24.111 ;
    END
  END rd_out[167]
  PIN rd_out[168]
    DIRECTION OUTPUT ;
    USE SIGNAL ;
    SHAPE ABUTMENT ;
    PORT
      LAYER M4 ;
      RECT 0.000 24.231 0.024 24.255 ;
    END
  END rd_out[168]
  PIN rd_out[169]
    DIRECTION OUTPUT ;
    USE SIGNAL ;
    SHAPE ABUTMENT ;
    PORT
      LAYER M4 ;
      RECT 0.000 24.375 0.024 24.399 ;
    END
  END rd_out[169]
  PIN rd_out[170]
    DIRECTION OUTPUT ;
    USE SIGNAL ;
    SHAPE ABUTMENT ;
    PORT
      LAYER M4 ;
      RECT 0.000 24.519 0.024 24.543 ;
    END
  END rd_out[170]
  PIN rd_out[171]
    DIRECTION OUTPUT ;
    USE SIGNAL ;
    SHAPE ABUTMENT ;
    PORT
      LAYER M4 ;
      RECT 0.000 24.663 0.024 24.687 ;
    END
  END rd_out[171]
  PIN rd_out[172]
    DIRECTION OUTPUT ;
    USE SIGNAL ;
    SHAPE ABUTMENT ;
    PORT
      LAYER M4 ;
      RECT 0.000 24.807 0.024 24.831 ;
    END
  END rd_out[172]
  PIN rd_out[173]
    DIRECTION OUTPUT ;
    USE SIGNAL ;
    SHAPE ABUTMENT ;
    PORT
      LAYER M4 ;
      RECT 0.000 24.951 0.024 24.975 ;
    END
  END rd_out[173]
  PIN rd_out[174]
    DIRECTION OUTPUT ;
    USE SIGNAL ;
    SHAPE ABUTMENT ;
    PORT
      LAYER M4 ;
      RECT 0.000 25.095 0.024 25.119 ;
    END
  END rd_out[174]
  PIN rd_out[175]
    DIRECTION OUTPUT ;
    USE SIGNAL ;
    SHAPE ABUTMENT ;
    PORT
      LAYER M4 ;
      RECT 0.000 25.239 0.024 25.263 ;
    END
  END rd_out[175]
  PIN rd_out[176]
    DIRECTION OUTPUT ;
    USE SIGNAL ;
    SHAPE ABUTMENT ;
    PORT
      LAYER M4 ;
      RECT 0.000 25.383 0.024 25.407 ;
    END
  END rd_out[176]
  PIN rd_out[177]
    DIRECTION OUTPUT ;
    USE SIGNAL ;
    SHAPE ABUTMENT ;
    PORT
      LAYER M4 ;
      RECT 0.000 25.527 0.024 25.551 ;
    END
  END rd_out[177]
  PIN rd_out[178]
    DIRECTION OUTPUT ;
    USE SIGNAL ;
    SHAPE ABUTMENT ;
    PORT
      LAYER M4 ;
      RECT 0.000 25.671 0.024 25.695 ;
    END
  END rd_out[178]
  PIN rd_out[179]
    DIRECTION OUTPUT ;
    USE SIGNAL ;
    SHAPE ABUTMENT ;
    PORT
      LAYER M4 ;
      RECT 0.000 25.815 0.024 25.839 ;
    END
  END rd_out[179]
  PIN rd_out[180]
    DIRECTION OUTPUT ;
    USE SIGNAL ;
    SHAPE ABUTMENT ;
    PORT
      LAYER M4 ;
      RECT 0.000 25.959 0.024 25.983 ;
    END
  END rd_out[180]
  PIN rd_out[181]
    DIRECTION OUTPUT ;
    USE SIGNAL ;
    SHAPE ABUTMENT ;
    PORT
      LAYER M4 ;
      RECT 0.000 26.103 0.024 26.127 ;
    END
  END rd_out[181]
  PIN rd_out[182]
    DIRECTION OUTPUT ;
    USE SIGNAL ;
    SHAPE ABUTMENT ;
    PORT
      LAYER M4 ;
      RECT 0.000 26.247 0.024 26.271 ;
    END
  END rd_out[182]
  PIN rd_out[183]
    DIRECTION OUTPUT ;
    USE SIGNAL ;
    SHAPE ABUTMENT ;
    PORT
      LAYER M4 ;
      RECT 0.000 26.391 0.024 26.415 ;
    END
  END rd_out[183]
  PIN rd_out[184]
    DIRECTION OUTPUT ;
    USE SIGNAL ;
    SHAPE ABUTMENT ;
    PORT
      LAYER M4 ;
      RECT 0.000 26.535 0.024 26.559 ;
    END
  END rd_out[184]
  PIN rd_out[185]
    DIRECTION OUTPUT ;
    USE SIGNAL ;
    SHAPE ABUTMENT ;
    PORT
      LAYER M4 ;
      RECT 0.000 26.679 0.024 26.703 ;
    END
  END rd_out[185]
  PIN rd_out[186]
    DIRECTION OUTPUT ;
    USE SIGNAL ;
    SHAPE ABUTMENT ;
    PORT
      LAYER M4 ;
      RECT 0.000 26.823 0.024 26.847 ;
    END
  END rd_out[186]
  PIN rd_out[187]
    DIRECTION OUTPUT ;
    USE SIGNAL ;
    SHAPE ABUTMENT ;
    PORT
      LAYER M4 ;
      RECT 0.000 26.967 0.024 26.991 ;
    END
  END rd_out[187]
  PIN rd_out[188]
    DIRECTION OUTPUT ;
    USE SIGNAL ;
    SHAPE ABUTMENT ;
    PORT
      LAYER M4 ;
      RECT 0.000 27.111 0.024 27.135 ;
    END
  END rd_out[188]
  PIN rd_out[189]
    DIRECTION OUTPUT ;
    USE SIGNAL ;
    SHAPE ABUTMENT ;
    PORT
      LAYER M4 ;
      RECT 0.000 27.255 0.024 27.279 ;
    END
  END rd_out[189]
  PIN rd_out[190]
    DIRECTION OUTPUT ;
    USE SIGNAL ;
    SHAPE ABUTMENT ;
    PORT
      LAYER M4 ;
      RECT 0.000 27.399 0.024 27.423 ;
    END
  END rd_out[190]
  PIN rd_out[191]
    DIRECTION OUTPUT ;
    USE SIGNAL ;
    SHAPE ABUTMENT ;
    PORT
      LAYER M4 ;
      RECT 0.000 27.543 0.024 27.567 ;
    END
  END rd_out[191]
  PIN rd_out[192]
    DIRECTION OUTPUT ;
    USE SIGNAL ;
    SHAPE ABUTMENT ;
    PORT
      LAYER M4 ;
      RECT 0.000 27.687 0.024 27.711 ;
    END
  END rd_out[192]
  PIN rd_out[193]
    DIRECTION OUTPUT ;
    USE SIGNAL ;
    SHAPE ABUTMENT ;
    PORT
      LAYER M4 ;
      RECT 0.000 27.831 0.024 27.855 ;
    END
  END rd_out[193]
  PIN rd_out[194]
    DIRECTION OUTPUT ;
    USE SIGNAL ;
    SHAPE ABUTMENT ;
    PORT
      LAYER M4 ;
      RECT 0.000 27.975 0.024 27.999 ;
    END
  END rd_out[194]
  PIN rd_out[195]
    DIRECTION OUTPUT ;
    USE SIGNAL ;
    SHAPE ABUTMENT ;
    PORT
      LAYER M4 ;
      RECT 0.000 28.119 0.024 28.143 ;
    END
  END rd_out[195]
  PIN rd_out[196]
    DIRECTION OUTPUT ;
    USE SIGNAL ;
    SHAPE ABUTMENT ;
    PORT
      LAYER M4 ;
      RECT 0.000 28.263 0.024 28.287 ;
    END
  END rd_out[196]
  PIN rd_out[197]
    DIRECTION OUTPUT ;
    USE SIGNAL ;
    SHAPE ABUTMENT ;
    PORT
      LAYER M4 ;
      RECT 0.000 28.407 0.024 28.431 ;
    END
  END rd_out[197]
  PIN rd_out[198]
    DIRECTION OUTPUT ;
    USE SIGNAL ;
    SHAPE ABUTMENT ;
    PORT
      LAYER M4 ;
      RECT 0.000 28.551 0.024 28.575 ;
    END
  END rd_out[198]
  PIN rd_out[199]
    DIRECTION OUTPUT ;
    USE SIGNAL ;
    SHAPE ABUTMENT ;
    PORT
      LAYER M4 ;
      RECT 0.000 28.695 0.024 28.719 ;
    END
  END rd_out[199]
  PIN rd_out[200]
    DIRECTION OUTPUT ;
    USE SIGNAL ;
    SHAPE ABUTMENT ;
    PORT
      LAYER M4 ;
      RECT 0.000 28.839 0.024 28.863 ;
    END
  END rd_out[200]
  PIN rd_out[201]
    DIRECTION OUTPUT ;
    USE SIGNAL ;
    SHAPE ABUTMENT ;
    PORT
      LAYER M4 ;
      RECT 0.000 28.983 0.024 29.007 ;
    END
  END rd_out[201]
  PIN rd_out[202]
    DIRECTION OUTPUT ;
    USE SIGNAL ;
    SHAPE ABUTMENT ;
    PORT
      LAYER M4 ;
      RECT 0.000 29.127 0.024 29.151 ;
    END
  END rd_out[202]
  PIN rd_out[203]
    DIRECTION OUTPUT ;
    USE SIGNAL ;
    SHAPE ABUTMENT ;
    PORT
      LAYER M4 ;
      RECT 0.000 29.271 0.024 29.295 ;
    END
  END rd_out[203]
  PIN rd_out[204]
    DIRECTION OUTPUT ;
    USE SIGNAL ;
    SHAPE ABUTMENT ;
    PORT
      LAYER M4 ;
      RECT 0.000 29.415 0.024 29.439 ;
    END
  END rd_out[204]
  PIN rd_out[205]
    DIRECTION OUTPUT ;
    USE SIGNAL ;
    SHAPE ABUTMENT ;
    PORT
      LAYER M4 ;
      RECT 0.000 29.559 0.024 29.583 ;
    END
  END rd_out[205]
  PIN rd_out[206]
    DIRECTION OUTPUT ;
    USE SIGNAL ;
    SHAPE ABUTMENT ;
    PORT
      LAYER M4 ;
      RECT 0.000 29.703 0.024 29.727 ;
    END
  END rd_out[206]
  PIN rd_out[207]
    DIRECTION OUTPUT ;
    USE SIGNAL ;
    SHAPE ABUTMENT ;
    PORT
      LAYER M4 ;
      RECT 0.000 29.847 0.024 29.871 ;
    END
  END rd_out[207]
  PIN rd_out[208]
    DIRECTION OUTPUT ;
    USE SIGNAL ;
    SHAPE ABUTMENT ;
    PORT
      LAYER M4 ;
      RECT 0.000 29.991 0.024 30.015 ;
    END
  END rd_out[208]
  PIN rd_out[209]
    DIRECTION OUTPUT ;
    USE SIGNAL ;
    SHAPE ABUTMENT ;
    PORT
      LAYER M4 ;
      RECT 0.000 30.135 0.024 30.159 ;
    END
  END rd_out[209]
  PIN rd_out[210]
    DIRECTION OUTPUT ;
    USE SIGNAL ;
    SHAPE ABUTMENT ;
    PORT
      LAYER M4 ;
      RECT 0.000 30.279 0.024 30.303 ;
    END
  END rd_out[210]
  PIN rd_out[211]
    DIRECTION OUTPUT ;
    USE SIGNAL ;
    SHAPE ABUTMENT ;
    PORT
      LAYER M4 ;
      RECT 0.000 30.423 0.024 30.447 ;
    END
  END rd_out[211]
  PIN rd_out[212]
    DIRECTION OUTPUT ;
    USE SIGNAL ;
    SHAPE ABUTMENT ;
    PORT
      LAYER M4 ;
      RECT 0.000 30.567 0.024 30.591 ;
    END
  END rd_out[212]
  PIN rd_out[213]
    DIRECTION OUTPUT ;
    USE SIGNAL ;
    SHAPE ABUTMENT ;
    PORT
      LAYER M4 ;
      RECT 0.000 30.711 0.024 30.735 ;
    END
  END rd_out[213]
  PIN rd_out[214]
    DIRECTION OUTPUT ;
    USE SIGNAL ;
    SHAPE ABUTMENT ;
    PORT
      LAYER M4 ;
      RECT 0.000 30.855 0.024 30.879 ;
    END
  END rd_out[214]
  PIN rd_out[215]
    DIRECTION OUTPUT ;
    USE SIGNAL ;
    SHAPE ABUTMENT ;
    PORT
      LAYER M4 ;
      RECT 0.000 30.999 0.024 31.023 ;
    END
  END rd_out[215]
  PIN rd_out[216]
    DIRECTION OUTPUT ;
    USE SIGNAL ;
    SHAPE ABUTMENT ;
    PORT
      LAYER M4 ;
      RECT 0.000 31.143 0.024 31.167 ;
    END
  END rd_out[216]
  PIN rd_out[217]
    DIRECTION OUTPUT ;
    USE SIGNAL ;
    SHAPE ABUTMENT ;
    PORT
      LAYER M4 ;
      RECT 0.000 31.287 0.024 31.311 ;
    END
  END rd_out[217]
  PIN rd_out[218]
    DIRECTION OUTPUT ;
    USE SIGNAL ;
    SHAPE ABUTMENT ;
    PORT
      LAYER M4 ;
      RECT 0.000 31.431 0.024 31.455 ;
    END
  END rd_out[218]
  PIN rd_out[219]
    DIRECTION OUTPUT ;
    USE SIGNAL ;
    SHAPE ABUTMENT ;
    PORT
      LAYER M4 ;
      RECT 0.000 31.575 0.024 31.599 ;
    END
  END rd_out[219]
  PIN rd_out[220]
    DIRECTION OUTPUT ;
    USE SIGNAL ;
    SHAPE ABUTMENT ;
    PORT
      LAYER M4 ;
      RECT 0.000 31.719 0.024 31.743 ;
    END
  END rd_out[220]
  PIN rd_out[221]
    DIRECTION OUTPUT ;
    USE SIGNAL ;
    SHAPE ABUTMENT ;
    PORT
      LAYER M4 ;
      RECT 0.000 31.863 0.024 31.887 ;
    END
  END rd_out[221]
  PIN rd_out[222]
    DIRECTION OUTPUT ;
    USE SIGNAL ;
    SHAPE ABUTMENT ;
    PORT
      LAYER M4 ;
      RECT 0.000 32.007 0.024 32.031 ;
    END
  END rd_out[222]
  PIN rd_out[223]
    DIRECTION OUTPUT ;
    USE SIGNAL ;
    SHAPE ABUTMENT ;
    PORT
      LAYER M4 ;
      RECT 0.000 32.151 0.024 32.175 ;
    END
  END rd_out[223]
  PIN rd_out[224]
    DIRECTION OUTPUT ;
    USE SIGNAL ;
    SHAPE ABUTMENT ;
    PORT
      LAYER M4 ;
      RECT 0.000 32.295 0.024 32.319 ;
    END
  END rd_out[224]
  PIN rd_out[225]
    DIRECTION OUTPUT ;
    USE SIGNAL ;
    SHAPE ABUTMENT ;
    PORT
      LAYER M4 ;
      RECT 0.000 32.439 0.024 32.463 ;
    END
  END rd_out[225]
  PIN rd_out[226]
    DIRECTION OUTPUT ;
    USE SIGNAL ;
    SHAPE ABUTMENT ;
    PORT
      LAYER M4 ;
      RECT 0.000 32.583 0.024 32.607 ;
    END
  END rd_out[226]
  PIN rd_out[227]
    DIRECTION OUTPUT ;
    USE SIGNAL ;
    SHAPE ABUTMENT ;
    PORT
      LAYER M4 ;
      RECT 0.000 32.727 0.024 32.751 ;
    END
  END rd_out[227]
  PIN rd_out[228]
    DIRECTION OUTPUT ;
    USE SIGNAL ;
    SHAPE ABUTMENT ;
    PORT
      LAYER M4 ;
      RECT 0.000 32.871 0.024 32.895 ;
    END
  END rd_out[228]
  PIN rd_out[229]
    DIRECTION OUTPUT ;
    USE SIGNAL ;
    SHAPE ABUTMENT ;
    PORT
      LAYER M4 ;
      RECT 0.000 33.015 0.024 33.039 ;
    END
  END rd_out[229]
  PIN rd_out[230]
    DIRECTION OUTPUT ;
    USE SIGNAL ;
    SHAPE ABUTMENT ;
    PORT
      LAYER M4 ;
      RECT 0.000 33.159 0.024 33.183 ;
    END
  END rd_out[230]
  PIN rd_out[231]
    DIRECTION OUTPUT ;
    USE SIGNAL ;
    SHAPE ABUTMENT ;
    PORT
      LAYER M4 ;
      RECT 0.000 33.303 0.024 33.327 ;
    END
  END rd_out[231]
  PIN rd_out[232]
    DIRECTION OUTPUT ;
    USE SIGNAL ;
    SHAPE ABUTMENT ;
    PORT
      LAYER M4 ;
      RECT 0.000 33.447 0.024 33.471 ;
    END
  END rd_out[232]
  PIN rd_out[233]
    DIRECTION OUTPUT ;
    USE SIGNAL ;
    SHAPE ABUTMENT ;
    PORT
      LAYER M4 ;
      RECT 0.000 33.591 0.024 33.615 ;
    END
  END rd_out[233]
  PIN rd_out[234]
    DIRECTION OUTPUT ;
    USE SIGNAL ;
    SHAPE ABUTMENT ;
    PORT
      LAYER M4 ;
      RECT 0.000 33.735 0.024 33.759 ;
    END
  END rd_out[234]
  PIN rd_out[235]
    DIRECTION OUTPUT ;
    USE SIGNAL ;
    SHAPE ABUTMENT ;
    PORT
      LAYER M4 ;
      RECT 0.000 33.879 0.024 33.903 ;
    END
  END rd_out[235]
  PIN rd_out[236]
    DIRECTION OUTPUT ;
    USE SIGNAL ;
    SHAPE ABUTMENT ;
    PORT
      LAYER M4 ;
      RECT 0.000 34.023 0.024 34.047 ;
    END
  END rd_out[236]
  PIN rd_out[237]
    DIRECTION OUTPUT ;
    USE SIGNAL ;
    SHAPE ABUTMENT ;
    PORT
      LAYER M4 ;
      RECT 0.000 34.167 0.024 34.191 ;
    END
  END rd_out[237]
  PIN rd_out[238]
    DIRECTION OUTPUT ;
    USE SIGNAL ;
    SHAPE ABUTMENT ;
    PORT
      LAYER M4 ;
      RECT 0.000 34.311 0.024 34.335 ;
    END
  END rd_out[238]
  PIN rd_out[239]
    DIRECTION OUTPUT ;
    USE SIGNAL ;
    SHAPE ABUTMENT ;
    PORT
      LAYER M4 ;
      RECT 0.000 34.455 0.024 34.479 ;
    END
  END rd_out[239]
  PIN rd_out[240]
    DIRECTION OUTPUT ;
    USE SIGNAL ;
    SHAPE ABUTMENT ;
    PORT
      LAYER M4 ;
      RECT 0.000 34.599 0.024 34.623 ;
    END
  END rd_out[240]
  PIN rd_out[241]
    DIRECTION OUTPUT ;
    USE SIGNAL ;
    SHAPE ABUTMENT ;
    PORT
      LAYER M4 ;
      RECT 0.000 34.743 0.024 34.767 ;
    END
  END rd_out[241]
  PIN rd_out[242]
    DIRECTION OUTPUT ;
    USE SIGNAL ;
    SHAPE ABUTMENT ;
    PORT
      LAYER M4 ;
      RECT 0.000 34.887 0.024 34.911 ;
    END
  END rd_out[242]
  PIN rd_out[243]
    DIRECTION OUTPUT ;
    USE SIGNAL ;
    SHAPE ABUTMENT ;
    PORT
      LAYER M4 ;
      RECT 0.000 35.031 0.024 35.055 ;
    END
  END rd_out[243]
  PIN rd_out[244]
    DIRECTION OUTPUT ;
    USE SIGNAL ;
    SHAPE ABUTMENT ;
    PORT
      LAYER M4 ;
      RECT 0.000 35.175 0.024 35.199 ;
    END
  END rd_out[244]
  PIN rd_out[245]
    DIRECTION OUTPUT ;
    USE SIGNAL ;
    SHAPE ABUTMENT ;
    PORT
      LAYER M4 ;
      RECT 0.000 35.319 0.024 35.343 ;
    END
  END rd_out[245]
  PIN rd_out[246]
    DIRECTION OUTPUT ;
    USE SIGNAL ;
    SHAPE ABUTMENT ;
    PORT
      LAYER M4 ;
      RECT 0.000 35.463 0.024 35.487 ;
    END
  END rd_out[246]
  PIN rd_out[247]
    DIRECTION OUTPUT ;
    USE SIGNAL ;
    SHAPE ABUTMENT ;
    PORT
      LAYER M4 ;
      RECT 0.000 35.607 0.024 35.631 ;
    END
  END rd_out[247]
  PIN rd_out[248]
    DIRECTION OUTPUT ;
    USE SIGNAL ;
    SHAPE ABUTMENT ;
    PORT
      LAYER M4 ;
      RECT 0.000 35.751 0.024 35.775 ;
    END
  END rd_out[248]
  PIN rd_out[249]
    DIRECTION OUTPUT ;
    USE SIGNAL ;
    SHAPE ABUTMENT ;
    PORT
      LAYER M4 ;
      RECT 0.000 35.895 0.024 35.919 ;
    END
  END rd_out[249]
  PIN rd_out[250]
    DIRECTION OUTPUT ;
    USE SIGNAL ;
    SHAPE ABUTMENT ;
    PORT
      LAYER M4 ;
      RECT 0.000 36.039 0.024 36.063 ;
    END
  END rd_out[250]
  PIN rd_out[251]
    DIRECTION OUTPUT ;
    USE SIGNAL ;
    SHAPE ABUTMENT ;
    PORT
      LAYER M4 ;
      RECT 0.000 36.183 0.024 36.207 ;
    END
  END rd_out[251]
  PIN rd_out[252]
    DIRECTION OUTPUT ;
    USE SIGNAL ;
    SHAPE ABUTMENT ;
    PORT
      LAYER M4 ;
      RECT 0.000 36.327 0.024 36.351 ;
    END
  END rd_out[252]
  PIN rd_out[253]
    DIRECTION OUTPUT ;
    USE SIGNAL ;
    SHAPE ABUTMENT ;
    PORT
      LAYER M4 ;
      RECT 0.000 36.471 0.024 36.495 ;
    END
  END rd_out[253]
  PIN rd_out[254]
    DIRECTION OUTPUT ;
    USE SIGNAL ;
    SHAPE ABUTMENT ;
    PORT
      LAYER M4 ;
      RECT 0.000 36.615 0.024 36.639 ;
    END
  END rd_out[254]
  PIN rd_out[255]
    DIRECTION OUTPUT ;
    USE SIGNAL ;
    SHAPE ABUTMENT ;
    PORT
      LAYER M4 ;
      RECT 0.000 36.759 0.024 36.783 ;
    END
  END rd_out[255]
  PIN wd_in[0]
    DIRECTION INPUT ;
    USE SIGNAL ;
    SHAPE ABUTMENT ;
    PORT
      LAYER M4 ;
      RECT 0.000 39.735 0.024 39.759 ;
    END
  END wd_in[0]
  PIN wd_in[1]
    DIRECTION INPUT ;
    USE SIGNAL ;
    SHAPE ABUTMENT ;
    PORT
      LAYER M4 ;
      RECT 0.000 39.879 0.024 39.903 ;
    END
  END wd_in[1]
  PIN wd_in[2]
    DIRECTION INPUT ;
    USE SIGNAL ;
    SHAPE ABUTMENT ;
    PORT
      LAYER M4 ;
      RECT 0.000 40.023 0.024 40.047 ;
    END
  END wd_in[2]
  PIN wd_in[3]
    DIRECTION INPUT ;
    USE SIGNAL ;
    SHAPE ABUTMENT ;
    PORT
      LAYER M4 ;
      RECT 0.000 40.167 0.024 40.191 ;
    END
  END wd_in[3]
  PIN wd_in[4]
    DIRECTION INPUT ;
    USE SIGNAL ;
    SHAPE ABUTMENT ;
    PORT
      LAYER M4 ;
      RECT 0.000 40.311 0.024 40.335 ;
    END
  END wd_in[4]
  PIN wd_in[5]
    DIRECTION INPUT ;
    USE SIGNAL ;
    SHAPE ABUTMENT ;
    PORT
      LAYER M4 ;
      RECT 0.000 40.455 0.024 40.479 ;
    END
  END wd_in[5]
  PIN wd_in[6]
    DIRECTION INPUT ;
    USE SIGNAL ;
    SHAPE ABUTMENT ;
    PORT
      LAYER M4 ;
      RECT 0.000 40.599 0.024 40.623 ;
    END
  END wd_in[6]
  PIN wd_in[7]
    DIRECTION INPUT ;
    USE SIGNAL ;
    SHAPE ABUTMENT ;
    PORT
      LAYER M4 ;
      RECT 0.000 40.743 0.024 40.767 ;
    END
  END wd_in[7]
  PIN wd_in[8]
    DIRECTION INPUT ;
    USE SIGNAL ;
    SHAPE ABUTMENT ;
    PORT
      LAYER M4 ;
      RECT 0.000 40.887 0.024 40.911 ;
    END
  END wd_in[8]
  PIN wd_in[9]
    DIRECTION INPUT ;
    USE SIGNAL ;
    SHAPE ABUTMENT ;
    PORT
      LAYER M4 ;
      RECT 0.000 41.031 0.024 41.055 ;
    END
  END wd_in[9]
  PIN wd_in[10]
    DIRECTION INPUT ;
    USE SIGNAL ;
    SHAPE ABUTMENT ;
    PORT
      LAYER M4 ;
      RECT 0.000 41.175 0.024 41.199 ;
    END
  END wd_in[10]
  PIN wd_in[11]
    DIRECTION INPUT ;
    USE SIGNAL ;
    SHAPE ABUTMENT ;
    PORT
      LAYER M4 ;
      RECT 0.000 41.319 0.024 41.343 ;
    END
  END wd_in[11]
  PIN wd_in[12]
    DIRECTION INPUT ;
    USE SIGNAL ;
    SHAPE ABUTMENT ;
    PORT
      LAYER M4 ;
      RECT 0.000 41.463 0.024 41.487 ;
    END
  END wd_in[12]
  PIN wd_in[13]
    DIRECTION INPUT ;
    USE SIGNAL ;
    SHAPE ABUTMENT ;
    PORT
      LAYER M4 ;
      RECT 0.000 41.607 0.024 41.631 ;
    END
  END wd_in[13]
  PIN wd_in[14]
    DIRECTION INPUT ;
    USE SIGNAL ;
    SHAPE ABUTMENT ;
    PORT
      LAYER M4 ;
      RECT 0.000 41.751 0.024 41.775 ;
    END
  END wd_in[14]
  PIN wd_in[15]
    DIRECTION INPUT ;
    USE SIGNAL ;
    SHAPE ABUTMENT ;
    PORT
      LAYER M4 ;
      RECT 0.000 41.895 0.024 41.919 ;
    END
  END wd_in[15]
  PIN wd_in[16]
    DIRECTION INPUT ;
    USE SIGNAL ;
    SHAPE ABUTMENT ;
    PORT
      LAYER M4 ;
      RECT 0.000 42.039 0.024 42.063 ;
    END
  END wd_in[16]
  PIN wd_in[17]
    DIRECTION INPUT ;
    USE SIGNAL ;
    SHAPE ABUTMENT ;
    PORT
      LAYER M4 ;
      RECT 0.000 42.183 0.024 42.207 ;
    END
  END wd_in[17]
  PIN wd_in[18]
    DIRECTION INPUT ;
    USE SIGNAL ;
    SHAPE ABUTMENT ;
    PORT
      LAYER M4 ;
      RECT 0.000 42.327 0.024 42.351 ;
    END
  END wd_in[18]
  PIN wd_in[19]
    DIRECTION INPUT ;
    USE SIGNAL ;
    SHAPE ABUTMENT ;
    PORT
      LAYER M4 ;
      RECT 0.000 42.471 0.024 42.495 ;
    END
  END wd_in[19]
  PIN wd_in[20]
    DIRECTION INPUT ;
    USE SIGNAL ;
    SHAPE ABUTMENT ;
    PORT
      LAYER M4 ;
      RECT 0.000 42.615 0.024 42.639 ;
    END
  END wd_in[20]
  PIN wd_in[21]
    DIRECTION INPUT ;
    USE SIGNAL ;
    SHAPE ABUTMENT ;
    PORT
      LAYER M4 ;
      RECT 0.000 42.759 0.024 42.783 ;
    END
  END wd_in[21]
  PIN wd_in[22]
    DIRECTION INPUT ;
    USE SIGNAL ;
    SHAPE ABUTMENT ;
    PORT
      LAYER M4 ;
      RECT 0.000 42.903 0.024 42.927 ;
    END
  END wd_in[22]
  PIN wd_in[23]
    DIRECTION INPUT ;
    USE SIGNAL ;
    SHAPE ABUTMENT ;
    PORT
      LAYER M4 ;
      RECT 0.000 43.047 0.024 43.071 ;
    END
  END wd_in[23]
  PIN wd_in[24]
    DIRECTION INPUT ;
    USE SIGNAL ;
    SHAPE ABUTMENT ;
    PORT
      LAYER M4 ;
      RECT 0.000 43.191 0.024 43.215 ;
    END
  END wd_in[24]
  PIN wd_in[25]
    DIRECTION INPUT ;
    USE SIGNAL ;
    SHAPE ABUTMENT ;
    PORT
      LAYER M4 ;
      RECT 0.000 43.335 0.024 43.359 ;
    END
  END wd_in[25]
  PIN wd_in[26]
    DIRECTION INPUT ;
    USE SIGNAL ;
    SHAPE ABUTMENT ;
    PORT
      LAYER M4 ;
      RECT 0.000 43.479 0.024 43.503 ;
    END
  END wd_in[26]
  PIN wd_in[27]
    DIRECTION INPUT ;
    USE SIGNAL ;
    SHAPE ABUTMENT ;
    PORT
      LAYER M4 ;
      RECT 0.000 43.623 0.024 43.647 ;
    END
  END wd_in[27]
  PIN wd_in[28]
    DIRECTION INPUT ;
    USE SIGNAL ;
    SHAPE ABUTMENT ;
    PORT
      LAYER M4 ;
      RECT 0.000 43.767 0.024 43.791 ;
    END
  END wd_in[28]
  PIN wd_in[29]
    DIRECTION INPUT ;
    USE SIGNAL ;
    SHAPE ABUTMENT ;
    PORT
      LAYER M4 ;
      RECT 0.000 43.911 0.024 43.935 ;
    END
  END wd_in[29]
  PIN wd_in[30]
    DIRECTION INPUT ;
    USE SIGNAL ;
    SHAPE ABUTMENT ;
    PORT
      LAYER M4 ;
      RECT 0.000 44.055 0.024 44.079 ;
    END
  END wd_in[30]
  PIN wd_in[31]
    DIRECTION INPUT ;
    USE SIGNAL ;
    SHAPE ABUTMENT ;
    PORT
      LAYER M4 ;
      RECT 0.000 44.199 0.024 44.223 ;
    END
  END wd_in[31]
  PIN wd_in[32]
    DIRECTION INPUT ;
    USE SIGNAL ;
    SHAPE ABUTMENT ;
    PORT
      LAYER M4 ;
      RECT 0.000 44.343 0.024 44.367 ;
    END
  END wd_in[32]
  PIN wd_in[33]
    DIRECTION INPUT ;
    USE SIGNAL ;
    SHAPE ABUTMENT ;
    PORT
      LAYER M4 ;
      RECT 0.000 44.487 0.024 44.511 ;
    END
  END wd_in[33]
  PIN wd_in[34]
    DIRECTION INPUT ;
    USE SIGNAL ;
    SHAPE ABUTMENT ;
    PORT
      LAYER M4 ;
      RECT 0.000 44.631 0.024 44.655 ;
    END
  END wd_in[34]
  PIN wd_in[35]
    DIRECTION INPUT ;
    USE SIGNAL ;
    SHAPE ABUTMENT ;
    PORT
      LAYER M4 ;
      RECT 0.000 44.775 0.024 44.799 ;
    END
  END wd_in[35]
  PIN wd_in[36]
    DIRECTION INPUT ;
    USE SIGNAL ;
    SHAPE ABUTMENT ;
    PORT
      LAYER M4 ;
      RECT 0.000 44.919 0.024 44.943 ;
    END
  END wd_in[36]
  PIN wd_in[37]
    DIRECTION INPUT ;
    USE SIGNAL ;
    SHAPE ABUTMENT ;
    PORT
      LAYER M4 ;
      RECT 0.000 45.063 0.024 45.087 ;
    END
  END wd_in[37]
  PIN wd_in[38]
    DIRECTION INPUT ;
    USE SIGNAL ;
    SHAPE ABUTMENT ;
    PORT
      LAYER M4 ;
      RECT 0.000 45.207 0.024 45.231 ;
    END
  END wd_in[38]
  PIN wd_in[39]
    DIRECTION INPUT ;
    USE SIGNAL ;
    SHAPE ABUTMENT ;
    PORT
      LAYER M4 ;
      RECT 0.000 45.351 0.024 45.375 ;
    END
  END wd_in[39]
  PIN wd_in[40]
    DIRECTION INPUT ;
    USE SIGNAL ;
    SHAPE ABUTMENT ;
    PORT
      LAYER M4 ;
      RECT 0.000 45.495 0.024 45.519 ;
    END
  END wd_in[40]
  PIN wd_in[41]
    DIRECTION INPUT ;
    USE SIGNAL ;
    SHAPE ABUTMENT ;
    PORT
      LAYER M4 ;
      RECT 0.000 45.639 0.024 45.663 ;
    END
  END wd_in[41]
  PIN wd_in[42]
    DIRECTION INPUT ;
    USE SIGNAL ;
    SHAPE ABUTMENT ;
    PORT
      LAYER M4 ;
      RECT 0.000 45.783 0.024 45.807 ;
    END
  END wd_in[42]
  PIN wd_in[43]
    DIRECTION INPUT ;
    USE SIGNAL ;
    SHAPE ABUTMENT ;
    PORT
      LAYER M4 ;
      RECT 0.000 45.927 0.024 45.951 ;
    END
  END wd_in[43]
  PIN wd_in[44]
    DIRECTION INPUT ;
    USE SIGNAL ;
    SHAPE ABUTMENT ;
    PORT
      LAYER M4 ;
      RECT 0.000 46.071 0.024 46.095 ;
    END
  END wd_in[44]
  PIN wd_in[45]
    DIRECTION INPUT ;
    USE SIGNAL ;
    SHAPE ABUTMENT ;
    PORT
      LAYER M4 ;
      RECT 0.000 46.215 0.024 46.239 ;
    END
  END wd_in[45]
  PIN wd_in[46]
    DIRECTION INPUT ;
    USE SIGNAL ;
    SHAPE ABUTMENT ;
    PORT
      LAYER M4 ;
      RECT 0.000 46.359 0.024 46.383 ;
    END
  END wd_in[46]
  PIN wd_in[47]
    DIRECTION INPUT ;
    USE SIGNAL ;
    SHAPE ABUTMENT ;
    PORT
      LAYER M4 ;
      RECT 0.000 46.503 0.024 46.527 ;
    END
  END wd_in[47]
  PIN wd_in[48]
    DIRECTION INPUT ;
    USE SIGNAL ;
    SHAPE ABUTMENT ;
    PORT
      LAYER M4 ;
      RECT 0.000 46.647 0.024 46.671 ;
    END
  END wd_in[48]
  PIN wd_in[49]
    DIRECTION INPUT ;
    USE SIGNAL ;
    SHAPE ABUTMENT ;
    PORT
      LAYER M4 ;
      RECT 0.000 46.791 0.024 46.815 ;
    END
  END wd_in[49]
  PIN wd_in[50]
    DIRECTION INPUT ;
    USE SIGNAL ;
    SHAPE ABUTMENT ;
    PORT
      LAYER M4 ;
      RECT 0.000 46.935 0.024 46.959 ;
    END
  END wd_in[50]
  PIN wd_in[51]
    DIRECTION INPUT ;
    USE SIGNAL ;
    SHAPE ABUTMENT ;
    PORT
      LAYER M4 ;
      RECT 0.000 47.079 0.024 47.103 ;
    END
  END wd_in[51]
  PIN wd_in[52]
    DIRECTION INPUT ;
    USE SIGNAL ;
    SHAPE ABUTMENT ;
    PORT
      LAYER M4 ;
      RECT 0.000 47.223 0.024 47.247 ;
    END
  END wd_in[52]
  PIN wd_in[53]
    DIRECTION INPUT ;
    USE SIGNAL ;
    SHAPE ABUTMENT ;
    PORT
      LAYER M4 ;
      RECT 0.000 47.367 0.024 47.391 ;
    END
  END wd_in[53]
  PIN wd_in[54]
    DIRECTION INPUT ;
    USE SIGNAL ;
    SHAPE ABUTMENT ;
    PORT
      LAYER M4 ;
      RECT 0.000 47.511 0.024 47.535 ;
    END
  END wd_in[54]
  PIN wd_in[55]
    DIRECTION INPUT ;
    USE SIGNAL ;
    SHAPE ABUTMENT ;
    PORT
      LAYER M4 ;
      RECT 0.000 47.655 0.024 47.679 ;
    END
  END wd_in[55]
  PIN wd_in[56]
    DIRECTION INPUT ;
    USE SIGNAL ;
    SHAPE ABUTMENT ;
    PORT
      LAYER M4 ;
      RECT 0.000 47.799 0.024 47.823 ;
    END
  END wd_in[56]
  PIN wd_in[57]
    DIRECTION INPUT ;
    USE SIGNAL ;
    SHAPE ABUTMENT ;
    PORT
      LAYER M4 ;
      RECT 0.000 47.943 0.024 47.967 ;
    END
  END wd_in[57]
  PIN wd_in[58]
    DIRECTION INPUT ;
    USE SIGNAL ;
    SHAPE ABUTMENT ;
    PORT
      LAYER M4 ;
      RECT 0.000 48.087 0.024 48.111 ;
    END
  END wd_in[58]
  PIN wd_in[59]
    DIRECTION INPUT ;
    USE SIGNAL ;
    SHAPE ABUTMENT ;
    PORT
      LAYER M4 ;
      RECT 0.000 48.231 0.024 48.255 ;
    END
  END wd_in[59]
  PIN wd_in[60]
    DIRECTION INPUT ;
    USE SIGNAL ;
    SHAPE ABUTMENT ;
    PORT
      LAYER M4 ;
      RECT 0.000 48.375 0.024 48.399 ;
    END
  END wd_in[60]
  PIN wd_in[61]
    DIRECTION INPUT ;
    USE SIGNAL ;
    SHAPE ABUTMENT ;
    PORT
      LAYER M4 ;
      RECT 0.000 48.519 0.024 48.543 ;
    END
  END wd_in[61]
  PIN wd_in[62]
    DIRECTION INPUT ;
    USE SIGNAL ;
    SHAPE ABUTMENT ;
    PORT
      LAYER M4 ;
      RECT 0.000 48.663 0.024 48.687 ;
    END
  END wd_in[62]
  PIN wd_in[63]
    DIRECTION INPUT ;
    USE SIGNAL ;
    SHAPE ABUTMENT ;
    PORT
      LAYER M4 ;
      RECT 0.000 48.807 0.024 48.831 ;
    END
  END wd_in[63]
  PIN wd_in[64]
    DIRECTION INPUT ;
    USE SIGNAL ;
    SHAPE ABUTMENT ;
    PORT
      LAYER M4 ;
      RECT 0.000 48.951 0.024 48.975 ;
    END
  END wd_in[64]
  PIN wd_in[65]
    DIRECTION INPUT ;
    USE SIGNAL ;
    SHAPE ABUTMENT ;
    PORT
      LAYER M4 ;
      RECT 0.000 49.095 0.024 49.119 ;
    END
  END wd_in[65]
  PIN wd_in[66]
    DIRECTION INPUT ;
    USE SIGNAL ;
    SHAPE ABUTMENT ;
    PORT
      LAYER M4 ;
      RECT 0.000 49.239 0.024 49.263 ;
    END
  END wd_in[66]
  PIN wd_in[67]
    DIRECTION INPUT ;
    USE SIGNAL ;
    SHAPE ABUTMENT ;
    PORT
      LAYER M4 ;
      RECT 0.000 49.383 0.024 49.407 ;
    END
  END wd_in[67]
  PIN wd_in[68]
    DIRECTION INPUT ;
    USE SIGNAL ;
    SHAPE ABUTMENT ;
    PORT
      LAYER M4 ;
      RECT 0.000 49.527 0.024 49.551 ;
    END
  END wd_in[68]
  PIN wd_in[69]
    DIRECTION INPUT ;
    USE SIGNAL ;
    SHAPE ABUTMENT ;
    PORT
      LAYER M4 ;
      RECT 0.000 49.671 0.024 49.695 ;
    END
  END wd_in[69]
  PIN wd_in[70]
    DIRECTION INPUT ;
    USE SIGNAL ;
    SHAPE ABUTMENT ;
    PORT
      LAYER M4 ;
      RECT 0.000 49.815 0.024 49.839 ;
    END
  END wd_in[70]
  PIN wd_in[71]
    DIRECTION INPUT ;
    USE SIGNAL ;
    SHAPE ABUTMENT ;
    PORT
      LAYER M4 ;
      RECT 0.000 49.959 0.024 49.983 ;
    END
  END wd_in[71]
  PIN wd_in[72]
    DIRECTION INPUT ;
    USE SIGNAL ;
    SHAPE ABUTMENT ;
    PORT
      LAYER M4 ;
      RECT 0.000 50.103 0.024 50.127 ;
    END
  END wd_in[72]
  PIN wd_in[73]
    DIRECTION INPUT ;
    USE SIGNAL ;
    SHAPE ABUTMENT ;
    PORT
      LAYER M4 ;
      RECT 0.000 50.247 0.024 50.271 ;
    END
  END wd_in[73]
  PIN wd_in[74]
    DIRECTION INPUT ;
    USE SIGNAL ;
    SHAPE ABUTMENT ;
    PORT
      LAYER M4 ;
      RECT 0.000 50.391 0.024 50.415 ;
    END
  END wd_in[74]
  PIN wd_in[75]
    DIRECTION INPUT ;
    USE SIGNAL ;
    SHAPE ABUTMENT ;
    PORT
      LAYER M4 ;
      RECT 0.000 50.535 0.024 50.559 ;
    END
  END wd_in[75]
  PIN wd_in[76]
    DIRECTION INPUT ;
    USE SIGNAL ;
    SHAPE ABUTMENT ;
    PORT
      LAYER M4 ;
      RECT 0.000 50.679 0.024 50.703 ;
    END
  END wd_in[76]
  PIN wd_in[77]
    DIRECTION INPUT ;
    USE SIGNAL ;
    SHAPE ABUTMENT ;
    PORT
      LAYER M4 ;
      RECT 0.000 50.823 0.024 50.847 ;
    END
  END wd_in[77]
  PIN wd_in[78]
    DIRECTION INPUT ;
    USE SIGNAL ;
    SHAPE ABUTMENT ;
    PORT
      LAYER M4 ;
      RECT 0.000 50.967 0.024 50.991 ;
    END
  END wd_in[78]
  PIN wd_in[79]
    DIRECTION INPUT ;
    USE SIGNAL ;
    SHAPE ABUTMENT ;
    PORT
      LAYER M4 ;
      RECT 0.000 51.111 0.024 51.135 ;
    END
  END wd_in[79]
  PIN wd_in[80]
    DIRECTION INPUT ;
    USE SIGNAL ;
    SHAPE ABUTMENT ;
    PORT
      LAYER M4 ;
      RECT 0.000 51.255 0.024 51.279 ;
    END
  END wd_in[80]
  PIN wd_in[81]
    DIRECTION INPUT ;
    USE SIGNAL ;
    SHAPE ABUTMENT ;
    PORT
      LAYER M4 ;
      RECT 0.000 51.399 0.024 51.423 ;
    END
  END wd_in[81]
  PIN wd_in[82]
    DIRECTION INPUT ;
    USE SIGNAL ;
    SHAPE ABUTMENT ;
    PORT
      LAYER M4 ;
      RECT 0.000 51.543 0.024 51.567 ;
    END
  END wd_in[82]
  PIN wd_in[83]
    DIRECTION INPUT ;
    USE SIGNAL ;
    SHAPE ABUTMENT ;
    PORT
      LAYER M4 ;
      RECT 0.000 51.687 0.024 51.711 ;
    END
  END wd_in[83]
  PIN wd_in[84]
    DIRECTION INPUT ;
    USE SIGNAL ;
    SHAPE ABUTMENT ;
    PORT
      LAYER M4 ;
      RECT 0.000 51.831 0.024 51.855 ;
    END
  END wd_in[84]
  PIN wd_in[85]
    DIRECTION INPUT ;
    USE SIGNAL ;
    SHAPE ABUTMENT ;
    PORT
      LAYER M4 ;
      RECT 0.000 51.975 0.024 51.999 ;
    END
  END wd_in[85]
  PIN wd_in[86]
    DIRECTION INPUT ;
    USE SIGNAL ;
    SHAPE ABUTMENT ;
    PORT
      LAYER M4 ;
      RECT 0.000 52.119 0.024 52.143 ;
    END
  END wd_in[86]
  PIN wd_in[87]
    DIRECTION INPUT ;
    USE SIGNAL ;
    SHAPE ABUTMENT ;
    PORT
      LAYER M4 ;
      RECT 0.000 52.263 0.024 52.287 ;
    END
  END wd_in[87]
  PIN wd_in[88]
    DIRECTION INPUT ;
    USE SIGNAL ;
    SHAPE ABUTMENT ;
    PORT
      LAYER M4 ;
      RECT 0.000 52.407 0.024 52.431 ;
    END
  END wd_in[88]
  PIN wd_in[89]
    DIRECTION INPUT ;
    USE SIGNAL ;
    SHAPE ABUTMENT ;
    PORT
      LAYER M4 ;
      RECT 0.000 52.551 0.024 52.575 ;
    END
  END wd_in[89]
  PIN wd_in[90]
    DIRECTION INPUT ;
    USE SIGNAL ;
    SHAPE ABUTMENT ;
    PORT
      LAYER M4 ;
      RECT 0.000 52.695 0.024 52.719 ;
    END
  END wd_in[90]
  PIN wd_in[91]
    DIRECTION INPUT ;
    USE SIGNAL ;
    SHAPE ABUTMENT ;
    PORT
      LAYER M4 ;
      RECT 0.000 52.839 0.024 52.863 ;
    END
  END wd_in[91]
  PIN wd_in[92]
    DIRECTION INPUT ;
    USE SIGNAL ;
    SHAPE ABUTMENT ;
    PORT
      LAYER M4 ;
      RECT 0.000 52.983 0.024 53.007 ;
    END
  END wd_in[92]
  PIN wd_in[93]
    DIRECTION INPUT ;
    USE SIGNAL ;
    SHAPE ABUTMENT ;
    PORT
      LAYER M4 ;
      RECT 0.000 53.127 0.024 53.151 ;
    END
  END wd_in[93]
  PIN wd_in[94]
    DIRECTION INPUT ;
    USE SIGNAL ;
    SHAPE ABUTMENT ;
    PORT
      LAYER M4 ;
      RECT 0.000 53.271 0.024 53.295 ;
    END
  END wd_in[94]
  PIN wd_in[95]
    DIRECTION INPUT ;
    USE SIGNAL ;
    SHAPE ABUTMENT ;
    PORT
      LAYER M4 ;
      RECT 0.000 53.415 0.024 53.439 ;
    END
  END wd_in[95]
  PIN wd_in[96]
    DIRECTION INPUT ;
    USE SIGNAL ;
    SHAPE ABUTMENT ;
    PORT
      LAYER M4 ;
      RECT 0.000 53.559 0.024 53.583 ;
    END
  END wd_in[96]
  PIN wd_in[97]
    DIRECTION INPUT ;
    USE SIGNAL ;
    SHAPE ABUTMENT ;
    PORT
      LAYER M4 ;
      RECT 0.000 53.703 0.024 53.727 ;
    END
  END wd_in[97]
  PIN wd_in[98]
    DIRECTION INPUT ;
    USE SIGNAL ;
    SHAPE ABUTMENT ;
    PORT
      LAYER M4 ;
      RECT 0.000 53.847 0.024 53.871 ;
    END
  END wd_in[98]
  PIN wd_in[99]
    DIRECTION INPUT ;
    USE SIGNAL ;
    SHAPE ABUTMENT ;
    PORT
      LAYER M4 ;
      RECT 0.000 53.991 0.024 54.015 ;
    END
  END wd_in[99]
  PIN wd_in[100]
    DIRECTION INPUT ;
    USE SIGNAL ;
    SHAPE ABUTMENT ;
    PORT
      LAYER M4 ;
      RECT 0.000 54.135 0.024 54.159 ;
    END
  END wd_in[100]
  PIN wd_in[101]
    DIRECTION INPUT ;
    USE SIGNAL ;
    SHAPE ABUTMENT ;
    PORT
      LAYER M4 ;
      RECT 0.000 54.279 0.024 54.303 ;
    END
  END wd_in[101]
  PIN wd_in[102]
    DIRECTION INPUT ;
    USE SIGNAL ;
    SHAPE ABUTMENT ;
    PORT
      LAYER M4 ;
      RECT 0.000 54.423 0.024 54.447 ;
    END
  END wd_in[102]
  PIN wd_in[103]
    DIRECTION INPUT ;
    USE SIGNAL ;
    SHAPE ABUTMENT ;
    PORT
      LAYER M4 ;
      RECT 0.000 54.567 0.024 54.591 ;
    END
  END wd_in[103]
  PIN wd_in[104]
    DIRECTION INPUT ;
    USE SIGNAL ;
    SHAPE ABUTMENT ;
    PORT
      LAYER M4 ;
      RECT 0.000 54.711 0.024 54.735 ;
    END
  END wd_in[104]
  PIN wd_in[105]
    DIRECTION INPUT ;
    USE SIGNAL ;
    SHAPE ABUTMENT ;
    PORT
      LAYER M4 ;
      RECT 0.000 54.855 0.024 54.879 ;
    END
  END wd_in[105]
  PIN wd_in[106]
    DIRECTION INPUT ;
    USE SIGNAL ;
    SHAPE ABUTMENT ;
    PORT
      LAYER M4 ;
      RECT 0.000 54.999 0.024 55.023 ;
    END
  END wd_in[106]
  PIN wd_in[107]
    DIRECTION INPUT ;
    USE SIGNAL ;
    SHAPE ABUTMENT ;
    PORT
      LAYER M4 ;
      RECT 0.000 55.143 0.024 55.167 ;
    END
  END wd_in[107]
  PIN wd_in[108]
    DIRECTION INPUT ;
    USE SIGNAL ;
    SHAPE ABUTMENT ;
    PORT
      LAYER M4 ;
      RECT 0.000 55.287 0.024 55.311 ;
    END
  END wd_in[108]
  PIN wd_in[109]
    DIRECTION INPUT ;
    USE SIGNAL ;
    SHAPE ABUTMENT ;
    PORT
      LAYER M4 ;
      RECT 0.000 55.431 0.024 55.455 ;
    END
  END wd_in[109]
  PIN wd_in[110]
    DIRECTION INPUT ;
    USE SIGNAL ;
    SHAPE ABUTMENT ;
    PORT
      LAYER M4 ;
      RECT 0.000 55.575 0.024 55.599 ;
    END
  END wd_in[110]
  PIN wd_in[111]
    DIRECTION INPUT ;
    USE SIGNAL ;
    SHAPE ABUTMENT ;
    PORT
      LAYER M4 ;
      RECT 0.000 55.719 0.024 55.743 ;
    END
  END wd_in[111]
  PIN wd_in[112]
    DIRECTION INPUT ;
    USE SIGNAL ;
    SHAPE ABUTMENT ;
    PORT
      LAYER M4 ;
      RECT 0.000 55.863 0.024 55.887 ;
    END
  END wd_in[112]
  PIN wd_in[113]
    DIRECTION INPUT ;
    USE SIGNAL ;
    SHAPE ABUTMENT ;
    PORT
      LAYER M4 ;
      RECT 0.000 56.007 0.024 56.031 ;
    END
  END wd_in[113]
  PIN wd_in[114]
    DIRECTION INPUT ;
    USE SIGNAL ;
    SHAPE ABUTMENT ;
    PORT
      LAYER M4 ;
      RECT 0.000 56.151 0.024 56.175 ;
    END
  END wd_in[114]
  PIN wd_in[115]
    DIRECTION INPUT ;
    USE SIGNAL ;
    SHAPE ABUTMENT ;
    PORT
      LAYER M4 ;
      RECT 0.000 56.295 0.024 56.319 ;
    END
  END wd_in[115]
  PIN wd_in[116]
    DIRECTION INPUT ;
    USE SIGNAL ;
    SHAPE ABUTMENT ;
    PORT
      LAYER M4 ;
      RECT 0.000 56.439 0.024 56.463 ;
    END
  END wd_in[116]
  PIN wd_in[117]
    DIRECTION INPUT ;
    USE SIGNAL ;
    SHAPE ABUTMENT ;
    PORT
      LAYER M4 ;
      RECT 0.000 56.583 0.024 56.607 ;
    END
  END wd_in[117]
  PIN wd_in[118]
    DIRECTION INPUT ;
    USE SIGNAL ;
    SHAPE ABUTMENT ;
    PORT
      LAYER M4 ;
      RECT 0.000 56.727 0.024 56.751 ;
    END
  END wd_in[118]
  PIN wd_in[119]
    DIRECTION INPUT ;
    USE SIGNAL ;
    SHAPE ABUTMENT ;
    PORT
      LAYER M4 ;
      RECT 0.000 56.871 0.024 56.895 ;
    END
  END wd_in[119]
  PIN wd_in[120]
    DIRECTION INPUT ;
    USE SIGNAL ;
    SHAPE ABUTMENT ;
    PORT
      LAYER M4 ;
      RECT 0.000 57.015 0.024 57.039 ;
    END
  END wd_in[120]
  PIN wd_in[121]
    DIRECTION INPUT ;
    USE SIGNAL ;
    SHAPE ABUTMENT ;
    PORT
      LAYER M4 ;
      RECT 0.000 57.159 0.024 57.183 ;
    END
  END wd_in[121]
  PIN wd_in[122]
    DIRECTION INPUT ;
    USE SIGNAL ;
    SHAPE ABUTMENT ;
    PORT
      LAYER M4 ;
      RECT 0.000 57.303 0.024 57.327 ;
    END
  END wd_in[122]
  PIN wd_in[123]
    DIRECTION INPUT ;
    USE SIGNAL ;
    SHAPE ABUTMENT ;
    PORT
      LAYER M4 ;
      RECT 0.000 57.447 0.024 57.471 ;
    END
  END wd_in[123]
  PIN wd_in[124]
    DIRECTION INPUT ;
    USE SIGNAL ;
    SHAPE ABUTMENT ;
    PORT
      LAYER M4 ;
      RECT 0.000 57.591 0.024 57.615 ;
    END
  END wd_in[124]
  PIN wd_in[125]
    DIRECTION INPUT ;
    USE SIGNAL ;
    SHAPE ABUTMENT ;
    PORT
      LAYER M4 ;
      RECT 0.000 57.735 0.024 57.759 ;
    END
  END wd_in[125]
  PIN wd_in[126]
    DIRECTION INPUT ;
    USE SIGNAL ;
    SHAPE ABUTMENT ;
    PORT
      LAYER M4 ;
      RECT 0.000 57.879 0.024 57.903 ;
    END
  END wd_in[126]
  PIN wd_in[127]
    DIRECTION INPUT ;
    USE SIGNAL ;
    SHAPE ABUTMENT ;
    PORT
      LAYER M4 ;
      RECT 0.000 58.023 0.024 58.047 ;
    END
  END wd_in[127]
  PIN wd_in[128]
    DIRECTION INPUT ;
    USE SIGNAL ;
    SHAPE ABUTMENT ;
    PORT
      LAYER M4 ;
      RECT 0.000 58.167 0.024 58.191 ;
    END
  END wd_in[128]
  PIN wd_in[129]
    DIRECTION INPUT ;
    USE SIGNAL ;
    SHAPE ABUTMENT ;
    PORT
      LAYER M4 ;
      RECT 0.000 58.311 0.024 58.335 ;
    END
  END wd_in[129]
  PIN wd_in[130]
    DIRECTION INPUT ;
    USE SIGNAL ;
    SHAPE ABUTMENT ;
    PORT
      LAYER M4 ;
      RECT 0.000 58.455 0.024 58.479 ;
    END
  END wd_in[130]
  PIN wd_in[131]
    DIRECTION INPUT ;
    USE SIGNAL ;
    SHAPE ABUTMENT ;
    PORT
      LAYER M4 ;
      RECT 0.000 58.599 0.024 58.623 ;
    END
  END wd_in[131]
  PIN wd_in[132]
    DIRECTION INPUT ;
    USE SIGNAL ;
    SHAPE ABUTMENT ;
    PORT
      LAYER M4 ;
      RECT 0.000 58.743 0.024 58.767 ;
    END
  END wd_in[132]
  PIN wd_in[133]
    DIRECTION INPUT ;
    USE SIGNAL ;
    SHAPE ABUTMENT ;
    PORT
      LAYER M4 ;
      RECT 0.000 58.887 0.024 58.911 ;
    END
  END wd_in[133]
  PIN wd_in[134]
    DIRECTION INPUT ;
    USE SIGNAL ;
    SHAPE ABUTMENT ;
    PORT
      LAYER M4 ;
      RECT 0.000 59.031 0.024 59.055 ;
    END
  END wd_in[134]
  PIN wd_in[135]
    DIRECTION INPUT ;
    USE SIGNAL ;
    SHAPE ABUTMENT ;
    PORT
      LAYER M4 ;
      RECT 0.000 59.175 0.024 59.199 ;
    END
  END wd_in[135]
  PIN wd_in[136]
    DIRECTION INPUT ;
    USE SIGNAL ;
    SHAPE ABUTMENT ;
    PORT
      LAYER M4 ;
      RECT 0.000 59.319 0.024 59.343 ;
    END
  END wd_in[136]
  PIN wd_in[137]
    DIRECTION INPUT ;
    USE SIGNAL ;
    SHAPE ABUTMENT ;
    PORT
      LAYER M4 ;
      RECT 0.000 59.463 0.024 59.487 ;
    END
  END wd_in[137]
  PIN wd_in[138]
    DIRECTION INPUT ;
    USE SIGNAL ;
    SHAPE ABUTMENT ;
    PORT
      LAYER M4 ;
      RECT 0.000 59.607 0.024 59.631 ;
    END
  END wd_in[138]
  PIN wd_in[139]
    DIRECTION INPUT ;
    USE SIGNAL ;
    SHAPE ABUTMENT ;
    PORT
      LAYER M4 ;
      RECT 0.000 59.751 0.024 59.775 ;
    END
  END wd_in[139]
  PIN wd_in[140]
    DIRECTION INPUT ;
    USE SIGNAL ;
    SHAPE ABUTMENT ;
    PORT
      LAYER M4 ;
      RECT 0.000 59.895 0.024 59.919 ;
    END
  END wd_in[140]
  PIN wd_in[141]
    DIRECTION INPUT ;
    USE SIGNAL ;
    SHAPE ABUTMENT ;
    PORT
      LAYER M4 ;
      RECT 0.000 60.039 0.024 60.063 ;
    END
  END wd_in[141]
  PIN wd_in[142]
    DIRECTION INPUT ;
    USE SIGNAL ;
    SHAPE ABUTMENT ;
    PORT
      LAYER M4 ;
      RECT 0.000 60.183 0.024 60.207 ;
    END
  END wd_in[142]
  PIN wd_in[143]
    DIRECTION INPUT ;
    USE SIGNAL ;
    SHAPE ABUTMENT ;
    PORT
      LAYER M4 ;
      RECT 0.000 60.327 0.024 60.351 ;
    END
  END wd_in[143]
  PIN wd_in[144]
    DIRECTION INPUT ;
    USE SIGNAL ;
    SHAPE ABUTMENT ;
    PORT
      LAYER M4 ;
      RECT 0.000 60.471 0.024 60.495 ;
    END
  END wd_in[144]
  PIN wd_in[145]
    DIRECTION INPUT ;
    USE SIGNAL ;
    SHAPE ABUTMENT ;
    PORT
      LAYER M4 ;
      RECT 0.000 60.615 0.024 60.639 ;
    END
  END wd_in[145]
  PIN wd_in[146]
    DIRECTION INPUT ;
    USE SIGNAL ;
    SHAPE ABUTMENT ;
    PORT
      LAYER M4 ;
      RECT 0.000 60.759 0.024 60.783 ;
    END
  END wd_in[146]
  PIN wd_in[147]
    DIRECTION INPUT ;
    USE SIGNAL ;
    SHAPE ABUTMENT ;
    PORT
      LAYER M4 ;
      RECT 0.000 60.903 0.024 60.927 ;
    END
  END wd_in[147]
  PIN wd_in[148]
    DIRECTION INPUT ;
    USE SIGNAL ;
    SHAPE ABUTMENT ;
    PORT
      LAYER M4 ;
      RECT 0.000 61.047 0.024 61.071 ;
    END
  END wd_in[148]
  PIN wd_in[149]
    DIRECTION INPUT ;
    USE SIGNAL ;
    SHAPE ABUTMENT ;
    PORT
      LAYER M4 ;
      RECT 0.000 61.191 0.024 61.215 ;
    END
  END wd_in[149]
  PIN wd_in[150]
    DIRECTION INPUT ;
    USE SIGNAL ;
    SHAPE ABUTMENT ;
    PORT
      LAYER M4 ;
      RECT 0.000 61.335 0.024 61.359 ;
    END
  END wd_in[150]
  PIN wd_in[151]
    DIRECTION INPUT ;
    USE SIGNAL ;
    SHAPE ABUTMENT ;
    PORT
      LAYER M4 ;
      RECT 0.000 61.479 0.024 61.503 ;
    END
  END wd_in[151]
  PIN wd_in[152]
    DIRECTION INPUT ;
    USE SIGNAL ;
    SHAPE ABUTMENT ;
    PORT
      LAYER M4 ;
      RECT 0.000 61.623 0.024 61.647 ;
    END
  END wd_in[152]
  PIN wd_in[153]
    DIRECTION INPUT ;
    USE SIGNAL ;
    SHAPE ABUTMENT ;
    PORT
      LAYER M4 ;
      RECT 0.000 61.767 0.024 61.791 ;
    END
  END wd_in[153]
  PIN wd_in[154]
    DIRECTION INPUT ;
    USE SIGNAL ;
    SHAPE ABUTMENT ;
    PORT
      LAYER M4 ;
      RECT 0.000 61.911 0.024 61.935 ;
    END
  END wd_in[154]
  PIN wd_in[155]
    DIRECTION INPUT ;
    USE SIGNAL ;
    SHAPE ABUTMENT ;
    PORT
      LAYER M4 ;
      RECT 0.000 62.055 0.024 62.079 ;
    END
  END wd_in[155]
  PIN wd_in[156]
    DIRECTION INPUT ;
    USE SIGNAL ;
    SHAPE ABUTMENT ;
    PORT
      LAYER M4 ;
      RECT 0.000 62.199 0.024 62.223 ;
    END
  END wd_in[156]
  PIN wd_in[157]
    DIRECTION INPUT ;
    USE SIGNAL ;
    SHAPE ABUTMENT ;
    PORT
      LAYER M4 ;
      RECT 0.000 62.343 0.024 62.367 ;
    END
  END wd_in[157]
  PIN wd_in[158]
    DIRECTION INPUT ;
    USE SIGNAL ;
    SHAPE ABUTMENT ;
    PORT
      LAYER M4 ;
      RECT 0.000 62.487 0.024 62.511 ;
    END
  END wd_in[158]
  PIN wd_in[159]
    DIRECTION INPUT ;
    USE SIGNAL ;
    SHAPE ABUTMENT ;
    PORT
      LAYER M4 ;
      RECT 0.000 62.631 0.024 62.655 ;
    END
  END wd_in[159]
  PIN wd_in[160]
    DIRECTION INPUT ;
    USE SIGNAL ;
    SHAPE ABUTMENT ;
    PORT
      LAYER M4 ;
      RECT 0.000 62.775 0.024 62.799 ;
    END
  END wd_in[160]
  PIN wd_in[161]
    DIRECTION INPUT ;
    USE SIGNAL ;
    SHAPE ABUTMENT ;
    PORT
      LAYER M4 ;
      RECT 0.000 62.919 0.024 62.943 ;
    END
  END wd_in[161]
  PIN wd_in[162]
    DIRECTION INPUT ;
    USE SIGNAL ;
    SHAPE ABUTMENT ;
    PORT
      LAYER M4 ;
      RECT 0.000 63.063 0.024 63.087 ;
    END
  END wd_in[162]
  PIN wd_in[163]
    DIRECTION INPUT ;
    USE SIGNAL ;
    SHAPE ABUTMENT ;
    PORT
      LAYER M4 ;
      RECT 0.000 63.207 0.024 63.231 ;
    END
  END wd_in[163]
  PIN wd_in[164]
    DIRECTION INPUT ;
    USE SIGNAL ;
    SHAPE ABUTMENT ;
    PORT
      LAYER M4 ;
      RECT 0.000 63.351 0.024 63.375 ;
    END
  END wd_in[164]
  PIN wd_in[165]
    DIRECTION INPUT ;
    USE SIGNAL ;
    SHAPE ABUTMENT ;
    PORT
      LAYER M4 ;
      RECT 0.000 63.495 0.024 63.519 ;
    END
  END wd_in[165]
  PIN wd_in[166]
    DIRECTION INPUT ;
    USE SIGNAL ;
    SHAPE ABUTMENT ;
    PORT
      LAYER M4 ;
      RECT 0.000 63.639 0.024 63.663 ;
    END
  END wd_in[166]
  PIN wd_in[167]
    DIRECTION INPUT ;
    USE SIGNAL ;
    SHAPE ABUTMENT ;
    PORT
      LAYER M4 ;
      RECT 0.000 63.783 0.024 63.807 ;
    END
  END wd_in[167]
  PIN wd_in[168]
    DIRECTION INPUT ;
    USE SIGNAL ;
    SHAPE ABUTMENT ;
    PORT
      LAYER M4 ;
      RECT 0.000 63.927 0.024 63.951 ;
    END
  END wd_in[168]
  PIN wd_in[169]
    DIRECTION INPUT ;
    USE SIGNAL ;
    SHAPE ABUTMENT ;
    PORT
      LAYER M4 ;
      RECT 0.000 64.071 0.024 64.095 ;
    END
  END wd_in[169]
  PIN wd_in[170]
    DIRECTION INPUT ;
    USE SIGNAL ;
    SHAPE ABUTMENT ;
    PORT
      LAYER M4 ;
      RECT 0.000 64.215 0.024 64.239 ;
    END
  END wd_in[170]
  PIN wd_in[171]
    DIRECTION INPUT ;
    USE SIGNAL ;
    SHAPE ABUTMENT ;
    PORT
      LAYER M4 ;
      RECT 0.000 64.359 0.024 64.383 ;
    END
  END wd_in[171]
  PIN wd_in[172]
    DIRECTION INPUT ;
    USE SIGNAL ;
    SHAPE ABUTMENT ;
    PORT
      LAYER M4 ;
      RECT 0.000 64.503 0.024 64.527 ;
    END
  END wd_in[172]
  PIN wd_in[173]
    DIRECTION INPUT ;
    USE SIGNAL ;
    SHAPE ABUTMENT ;
    PORT
      LAYER M4 ;
      RECT 0.000 64.647 0.024 64.671 ;
    END
  END wd_in[173]
  PIN wd_in[174]
    DIRECTION INPUT ;
    USE SIGNAL ;
    SHAPE ABUTMENT ;
    PORT
      LAYER M4 ;
      RECT 0.000 64.791 0.024 64.815 ;
    END
  END wd_in[174]
  PIN wd_in[175]
    DIRECTION INPUT ;
    USE SIGNAL ;
    SHAPE ABUTMENT ;
    PORT
      LAYER M4 ;
      RECT 0.000 64.935 0.024 64.959 ;
    END
  END wd_in[175]
  PIN wd_in[176]
    DIRECTION INPUT ;
    USE SIGNAL ;
    SHAPE ABUTMENT ;
    PORT
      LAYER M4 ;
      RECT 0.000 65.079 0.024 65.103 ;
    END
  END wd_in[176]
  PIN wd_in[177]
    DIRECTION INPUT ;
    USE SIGNAL ;
    SHAPE ABUTMENT ;
    PORT
      LAYER M4 ;
      RECT 0.000 65.223 0.024 65.247 ;
    END
  END wd_in[177]
  PIN wd_in[178]
    DIRECTION INPUT ;
    USE SIGNAL ;
    SHAPE ABUTMENT ;
    PORT
      LAYER M4 ;
      RECT 0.000 65.367 0.024 65.391 ;
    END
  END wd_in[178]
  PIN wd_in[179]
    DIRECTION INPUT ;
    USE SIGNAL ;
    SHAPE ABUTMENT ;
    PORT
      LAYER M4 ;
      RECT 0.000 65.511 0.024 65.535 ;
    END
  END wd_in[179]
  PIN wd_in[180]
    DIRECTION INPUT ;
    USE SIGNAL ;
    SHAPE ABUTMENT ;
    PORT
      LAYER M4 ;
      RECT 0.000 65.655 0.024 65.679 ;
    END
  END wd_in[180]
  PIN wd_in[181]
    DIRECTION INPUT ;
    USE SIGNAL ;
    SHAPE ABUTMENT ;
    PORT
      LAYER M4 ;
      RECT 0.000 65.799 0.024 65.823 ;
    END
  END wd_in[181]
  PIN wd_in[182]
    DIRECTION INPUT ;
    USE SIGNAL ;
    SHAPE ABUTMENT ;
    PORT
      LAYER M4 ;
      RECT 0.000 65.943 0.024 65.967 ;
    END
  END wd_in[182]
  PIN wd_in[183]
    DIRECTION INPUT ;
    USE SIGNAL ;
    SHAPE ABUTMENT ;
    PORT
      LAYER M4 ;
      RECT 0.000 66.087 0.024 66.111 ;
    END
  END wd_in[183]
  PIN wd_in[184]
    DIRECTION INPUT ;
    USE SIGNAL ;
    SHAPE ABUTMENT ;
    PORT
      LAYER M4 ;
      RECT 0.000 66.231 0.024 66.255 ;
    END
  END wd_in[184]
  PIN wd_in[185]
    DIRECTION INPUT ;
    USE SIGNAL ;
    SHAPE ABUTMENT ;
    PORT
      LAYER M4 ;
      RECT 0.000 66.375 0.024 66.399 ;
    END
  END wd_in[185]
  PIN wd_in[186]
    DIRECTION INPUT ;
    USE SIGNAL ;
    SHAPE ABUTMENT ;
    PORT
      LAYER M4 ;
      RECT 0.000 66.519 0.024 66.543 ;
    END
  END wd_in[186]
  PIN wd_in[187]
    DIRECTION INPUT ;
    USE SIGNAL ;
    SHAPE ABUTMENT ;
    PORT
      LAYER M4 ;
      RECT 0.000 66.663 0.024 66.687 ;
    END
  END wd_in[187]
  PIN wd_in[188]
    DIRECTION INPUT ;
    USE SIGNAL ;
    SHAPE ABUTMENT ;
    PORT
      LAYER M4 ;
      RECT 0.000 66.807 0.024 66.831 ;
    END
  END wd_in[188]
  PIN wd_in[189]
    DIRECTION INPUT ;
    USE SIGNAL ;
    SHAPE ABUTMENT ;
    PORT
      LAYER M4 ;
      RECT 0.000 66.951 0.024 66.975 ;
    END
  END wd_in[189]
  PIN wd_in[190]
    DIRECTION INPUT ;
    USE SIGNAL ;
    SHAPE ABUTMENT ;
    PORT
      LAYER M4 ;
      RECT 0.000 67.095 0.024 67.119 ;
    END
  END wd_in[190]
  PIN wd_in[191]
    DIRECTION INPUT ;
    USE SIGNAL ;
    SHAPE ABUTMENT ;
    PORT
      LAYER M4 ;
      RECT 0.000 67.239 0.024 67.263 ;
    END
  END wd_in[191]
  PIN wd_in[192]
    DIRECTION INPUT ;
    USE SIGNAL ;
    SHAPE ABUTMENT ;
    PORT
      LAYER M4 ;
      RECT 0.000 67.383 0.024 67.407 ;
    END
  END wd_in[192]
  PIN wd_in[193]
    DIRECTION INPUT ;
    USE SIGNAL ;
    SHAPE ABUTMENT ;
    PORT
      LAYER M4 ;
      RECT 0.000 67.527 0.024 67.551 ;
    END
  END wd_in[193]
  PIN wd_in[194]
    DIRECTION INPUT ;
    USE SIGNAL ;
    SHAPE ABUTMENT ;
    PORT
      LAYER M4 ;
      RECT 0.000 67.671 0.024 67.695 ;
    END
  END wd_in[194]
  PIN wd_in[195]
    DIRECTION INPUT ;
    USE SIGNAL ;
    SHAPE ABUTMENT ;
    PORT
      LAYER M4 ;
      RECT 0.000 67.815 0.024 67.839 ;
    END
  END wd_in[195]
  PIN wd_in[196]
    DIRECTION INPUT ;
    USE SIGNAL ;
    SHAPE ABUTMENT ;
    PORT
      LAYER M4 ;
      RECT 0.000 67.959 0.024 67.983 ;
    END
  END wd_in[196]
  PIN wd_in[197]
    DIRECTION INPUT ;
    USE SIGNAL ;
    SHAPE ABUTMENT ;
    PORT
      LAYER M4 ;
      RECT 0.000 68.103 0.024 68.127 ;
    END
  END wd_in[197]
  PIN wd_in[198]
    DIRECTION INPUT ;
    USE SIGNAL ;
    SHAPE ABUTMENT ;
    PORT
      LAYER M4 ;
      RECT 0.000 68.247 0.024 68.271 ;
    END
  END wd_in[198]
  PIN wd_in[199]
    DIRECTION INPUT ;
    USE SIGNAL ;
    SHAPE ABUTMENT ;
    PORT
      LAYER M4 ;
      RECT 0.000 68.391 0.024 68.415 ;
    END
  END wd_in[199]
  PIN wd_in[200]
    DIRECTION INPUT ;
    USE SIGNAL ;
    SHAPE ABUTMENT ;
    PORT
      LAYER M4 ;
      RECT 0.000 68.535 0.024 68.559 ;
    END
  END wd_in[200]
  PIN wd_in[201]
    DIRECTION INPUT ;
    USE SIGNAL ;
    SHAPE ABUTMENT ;
    PORT
      LAYER M4 ;
      RECT 0.000 68.679 0.024 68.703 ;
    END
  END wd_in[201]
  PIN wd_in[202]
    DIRECTION INPUT ;
    USE SIGNAL ;
    SHAPE ABUTMENT ;
    PORT
      LAYER M4 ;
      RECT 0.000 68.823 0.024 68.847 ;
    END
  END wd_in[202]
  PIN wd_in[203]
    DIRECTION INPUT ;
    USE SIGNAL ;
    SHAPE ABUTMENT ;
    PORT
      LAYER M4 ;
      RECT 0.000 68.967 0.024 68.991 ;
    END
  END wd_in[203]
  PIN wd_in[204]
    DIRECTION INPUT ;
    USE SIGNAL ;
    SHAPE ABUTMENT ;
    PORT
      LAYER M4 ;
      RECT 0.000 69.111 0.024 69.135 ;
    END
  END wd_in[204]
  PIN wd_in[205]
    DIRECTION INPUT ;
    USE SIGNAL ;
    SHAPE ABUTMENT ;
    PORT
      LAYER M4 ;
      RECT 0.000 69.255 0.024 69.279 ;
    END
  END wd_in[205]
  PIN wd_in[206]
    DIRECTION INPUT ;
    USE SIGNAL ;
    SHAPE ABUTMENT ;
    PORT
      LAYER M4 ;
      RECT 0.000 69.399 0.024 69.423 ;
    END
  END wd_in[206]
  PIN wd_in[207]
    DIRECTION INPUT ;
    USE SIGNAL ;
    SHAPE ABUTMENT ;
    PORT
      LAYER M4 ;
      RECT 0.000 69.543 0.024 69.567 ;
    END
  END wd_in[207]
  PIN wd_in[208]
    DIRECTION INPUT ;
    USE SIGNAL ;
    SHAPE ABUTMENT ;
    PORT
      LAYER M4 ;
      RECT 0.000 69.687 0.024 69.711 ;
    END
  END wd_in[208]
  PIN wd_in[209]
    DIRECTION INPUT ;
    USE SIGNAL ;
    SHAPE ABUTMENT ;
    PORT
      LAYER M4 ;
      RECT 0.000 69.831 0.024 69.855 ;
    END
  END wd_in[209]
  PIN wd_in[210]
    DIRECTION INPUT ;
    USE SIGNAL ;
    SHAPE ABUTMENT ;
    PORT
      LAYER M4 ;
      RECT 0.000 69.975 0.024 69.999 ;
    END
  END wd_in[210]
  PIN wd_in[211]
    DIRECTION INPUT ;
    USE SIGNAL ;
    SHAPE ABUTMENT ;
    PORT
      LAYER M4 ;
      RECT 0.000 70.119 0.024 70.143 ;
    END
  END wd_in[211]
  PIN wd_in[212]
    DIRECTION INPUT ;
    USE SIGNAL ;
    SHAPE ABUTMENT ;
    PORT
      LAYER M4 ;
      RECT 0.000 70.263 0.024 70.287 ;
    END
  END wd_in[212]
  PIN wd_in[213]
    DIRECTION INPUT ;
    USE SIGNAL ;
    SHAPE ABUTMENT ;
    PORT
      LAYER M4 ;
      RECT 0.000 70.407 0.024 70.431 ;
    END
  END wd_in[213]
  PIN wd_in[214]
    DIRECTION INPUT ;
    USE SIGNAL ;
    SHAPE ABUTMENT ;
    PORT
      LAYER M4 ;
      RECT 0.000 70.551 0.024 70.575 ;
    END
  END wd_in[214]
  PIN wd_in[215]
    DIRECTION INPUT ;
    USE SIGNAL ;
    SHAPE ABUTMENT ;
    PORT
      LAYER M4 ;
      RECT 0.000 70.695 0.024 70.719 ;
    END
  END wd_in[215]
  PIN wd_in[216]
    DIRECTION INPUT ;
    USE SIGNAL ;
    SHAPE ABUTMENT ;
    PORT
      LAYER M4 ;
      RECT 0.000 70.839 0.024 70.863 ;
    END
  END wd_in[216]
  PIN wd_in[217]
    DIRECTION INPUT ;
    USE SIGNAL ;
    SHAPE ABUTMENT ;
    PORT
      LAYER M4 ;
      RECT 0.000 70.983 0.024 71.007 ;
    END
  END wd_in[217]
  PIN wd_in[218]
    DIRECTION INPUT ;
    USE SIGNAL ;
    SHAPE ABUTMENT ;
    PORT
      LAYER M4 ;
      RECT 0.000 71.127 0.024 71.151 ;
    END
  END wd_in[218]
  PIN wd_in[219]
    DIRECTION INPUT ;
    USE SIGNAL ;
    SHAPE ABUTMENT ;
    PORT
      LAYER M4 ;
      RECT 0.000 71.271 0.024 71.295 ;
    END
  END wd_in[219]
  PIN wd_in[220]
    DIRECTION INPUT ;
    USE SIGNAL ;
    SHAPE ABUTMENT ;
    PORT
      LAYER M4 ;
      RECT 0.000 71.415 0.024 71.439 ;
    END
  END wd_in[220]
  PIN wd_in[221]
    DIRECTION INPUT ;
    USE SIGNAL ;
    SHAPE ABUTMENT ;
    PORT
      LAYER M4 ;
      RECT 0.000 71.559 0.024 71.583 ;
    END
  END wd_in[221]
  PIN wd_in[222]
    DIRECTION INPUT ;
    USE SIGNAL ;
    SHAPE ABUTMENT ;
    PORT
      LAYER M4 ;
      RECT 0.000 71.703 0.024 71.727 ;
    END
  END wd_in[222]
  PIN wd_in[223]
    DIRECTION INPUT ;
    USE SIGNAL ;
    SHAPE ABUTMENT ;
    PORT
      LAYER M4 ;
      RECT 0.000 71.847 0.024 71.871 ;
    END
  END wd_in[223]
  PIN wd_in[224]
    DIRECTION INPUT ;
    USE SIGNAL ;
    SHAPE ABUTMENT ;
    PORT
      LAYER M4 ;
      RECT 0.000 71.991 0.024 72.015 ;
    END
  END wd_in[224]
  PIN wd_in[225]
    DIRECTION INPUT ;
    USE SIGNAL ;
    SHAPE ABUTMENT ;
    PORT
      LAYER M4 ;
      RECT 0.000 72.135 0.024 72.159 ;
    END
  END wd_in[225]
  PIN wd_in[226]
    DIRECTION INPUT ;
    USE SIGNAL ;
    SHAPE ABUTMENT ;
    PORT
      LAYER M4 ;
      RECT 0.000 72.279 0.024 72.303 ;
    END
  END wd_in[226]
  PIN wd_in[227]
    DIRECTION INPUT ;
    USE SIGNAL ;
    SHAPE ABUTMENT ;
    PORT
      LAYER M4 ;
      RECT 0.000 72.423 0.024 72.447 ;
    END
  END wd_in[227]
  PIN wd_in[228]
    DIRECTION INPUT ;
    USE SIGNAL ;
    SHAPE ABUTMENT ;
    PORT
      LAYER M4 ;
      RECT 0.000 72.567 0.024 72.591 ;
    END
  END wd_in[228]
  PIN wd_in[229]
    DIRECTION INPUT ;
    USE SIGNAL ;
    SHAPE ABUTMENT ;
    PORT
      LAYER M4 ;
      RECT 0.000 72.711 0.024 72.735 ;
    END
  END wd_in[229]
  PIN wd_in[230]
    DIRECTION INPUT ;
    USE SIGNAL ;
    SHAPE ABUTMENT ;
    PORT
      LAYER M4 ;
      RECT 0.000 72.855 0.024 72.879 ;
    END
  END wd_in[230]
  PIN wd_in[231]
    DIRECTION INPUT ;
    USE SIGNAL ;
    SHAPE ABUTMENT ;
    PORT
      LAYER M4 ;
      RECT 0.000 72.999 0.024 73.023 ;
    END
  END wd_in[231]
  PIN wd_in[232]
    DIRECTION INPUT ;
    USE SIGNAL ;
    SHAPE ABUTMENT ;
    PORT
      LAYER M4 ;
      RECT 0.000 73.143 0.024 73.167 ;
    END
  END wd_in[232]
  PIN wd_in[233]
    DIRECTION INPUT ;
    USE SIGNAL ;
    SHAPE ABUTMENT ;
    PORT
      LAYER M4 ;
      RECT 0.000 73.287 0.024 73.311 ;
    END
  END wd_in[233]
  PIN wd_in[234]
    DIRECTION INPUT ;
    USE SIGNAL ;
    SHAPE ABUTMENT ;
    PORT
      LAYER M4 ;
      RECT 0.000 73.431 0.024 73.455 ;
    END
  END wd_in[234]
  PIN wd_in[235]
    DIRECTION INPUT ;
    USE SIGNAL ;
    SHAPE ABUTMENT ;
    PORT
      LAYER M4 ;
      RECT 0.000 73.575 0.024 73.599 ;
    END
  END wd_in[235]
  PIN wd_in[236]
    DIRECTION INPUT ;
    USE SIGNAL ;
    SHAPE ABUTMENT ;
    PORT
      LAYER M4 ;
      RECT 0.000 73.719 0.024 73.743 ;
    END
  END wd_in[236]
  PIN wd_in[237]
    DIRECTION INPUT ;
    USE SIGNAL ;
    SHAPE ABUTMENT ;
    PORT
      LAYER M4 ;
      RECT 0.000 73.863 0.024 73.887 ;
    END
  END wd_in[237]
  PIN wd_in[238]
    DIRECTION INPUT ;
    USE SIGNAL ;
    SHAPE ABUTMENT ;
    PORT
      LAYER M4 ;
      RECT 0.000 74.007 0.024 74.031 ;
    END
  END wd_in[238]
  PIN wd_in[239]
    DIRECTION INPUT ;
    USE SIGNAL ;
    SHAPE ABUTMENT ;
    PORT
      LAYER M4 ;
      RECT 0.000 74.151 0.024 74.175 ;
    END
  END wd_in[239]
  PIN wd_in[240]
    DIRECTION INPUT ;
    USE SIGNAL ;
    SHAPE ABUTMENT ;
    PORT
      LAYER M4 ;
      RECT 0.000 74.295 0.024 74.319 ;
    END
  END wd_in[240]
  PIN wd_in[241]
    DIRECTION INPUT ;
    USE SIGNAL ;
    SHAPE ABUTMENT ;
    PORT
      LAYER M4 ;
      RECT 0.000 74.439 0.024 74.463 ;
    END
  END wd_in[241]
  PIN wd_in[242]
    DIRECTION INPUT ;
    USE SIGNAL ;
    SHAPE ABUTMENT ;
    PORT
      LAYER M4 ;
      RECT 0.000 74.583 0.024 74.607 ;
    END
  END wd_in[242]
  PIN wd_in[243]
    DIRECTION INPUT ;
    USE SIGNAL ;
    SHAPE ABUTMENT ;
    PORT
      LAYER M4 ;
      RECT 0.000 74.727 0.024 74.751 ;
    END
  END wd_in[243]
  PIN wd_in[244]
    DIRECTION INPUT ;
    USE SIGNAL ;
    SHAPE ABUTMENT ;
    PORT
      LAYER M4 ;
      RECT 0.000 74.871 0.024 74.895 ;
    END
  END wd_in[244]
  PIN wd_in[245]
    DIRECTION INPUT ;
    USE SIGNAL ;
    SHAPE ABUTMENT ;
    PORT
      LAYER M4 ;
      RECT 0.000 75.015 0.024 75.039 ;
    END
  END wd_in[245]
  PIN wd_in[246]
    DIRECTION INPUT ;
    USE SIGNAL ;
    SHAPE ABUTMENT ;
    PORT
      LAYER M4 ;
      RECT 0.000 75.159 0.024 75.183 ;
    END
  END wd_in[246]
  PIN wd_in[247]
    DIRECTION INPUT ;
    USE SIGNAL ;
    SHAPE ABUTMENT ;
    PORT
      LAYER M4 ;
      RECT 0.000 75.303 0.024 75.327 ;
    END
  END wd_in[247]
  PIN wd_in[248]
    DIRECTION INPUT ;
    USE SIGNAL ;
    SHAPE ABUTMENT ;
    PORT
      LAYER M4 ;
      RECT 0.000 75.447 0.024 75.471 ;
    END
  END wd_in[248]
  PIN wd_in[249]
    DIRECTION INPUT ;
    USE SIGNAL ;
    SHAPE ABUTMENT ;
    PORT
      LAYER M4 ;
      RECT 0.000 75.591 0.024 75.615 ;
    END
  END wd_in[249]
  PIN wd_in[250]
    DIRECTION INPUT ;
    USE SIGNAL ;
    SHAPE ABUTMENT ;
    PORT
      LAYER M4 ;
      RECT 0.000 75.735 0.024 75.759 ;
    END
  END wd_in[250]
  PIN wd_in[251]
    DIRECTION INPUT ;
    USE SIGNAL ;
    SHAPE ABUTMENT ;
    PORT
      LAYER M4 ;
      RECT 0.000 75.879 0.024 75.903 ;
    END
  END wd_in[251]
  PIN wd_in[252]
    DIRECTION INPUT ;
    USE SIGNAL ;
    SHAPE ABUTMENT ;
    PORT
      LAYER M4 ;
      RECT 0.000 76.023 0.024 76.047 ;
    END
  END wd_in[252]
  PIN wd_in[253]
    DIRECTION INPUT ;
    USE SIGNAL ;
    SHAPE ABUTMENT ;
    PORT
      LAYER M4 ;
      RECT 0.000 76.167 0.024 76.191 ;
    END
  END wd_in[253]
  PIN wd_in[254]
    DIRECTION INPUT ;
    USE SIGNAL ;
    SHAPE ABUTMENT ;
    PORT
      LAYER M4 ;
      RECT 0.000 76.311 0.024 76.335 ;
    END
  END wd_in[254]
  PIN wd_in[255]
    DIRECTION INPUT ;
    USE SIGNAL ;
    SHAPE ABUTMENT ;
    PORT
      LAYER M4 ;
      RECT 0.000 76.455 0.024 76.479 ;
    END
  END wd_in[255]
  PIN addr_in[0]
    DIRECTION INPUT ;
    USE SIGNAL ;
    SHAPE ABUTMENT ;
    PORT
      LAYER M4 ;
      RECT 0.000 79.431 0.024 79.455 ;
    END
  END addr_in[0]
  PIN addr_in[1]
    DIRECTION INPUT ;
    USE SIGNAL ;
    SHAPE ABUTMENT ;
    PORT
      LAYER M4 ;
      RECT 0.000 79.575 0.024 79.599 ;
    END
  END addr_in[1]
  PIN addr_in[2]
    DIRECTION INPUT ;
    USE SIGNAL ;
    SHAPE ABUTMENT ;
    PORT
      LAYER M4 ;
      RECT 0.000 79.719 0.024 79.743 ;
    END
  END addr_in[2]
  PIN addr_in[3]
    DIRECTION INPUT ;
    USE SIGNAL ;
    SHAPE ABUTMENT ;
    PORT
      LAYER M4 ;
      RECT 0.000 79.863 0.024 79.887 ;
    END
  END addr_in[3]
  PIN addr_in[4]
    DIRECTION INPUT ;
    USE SIGNAL ;
    SHAPE ABUTMENT ;
    PORT
      LAYER M4 ;
      RECT 0.000 80.007 0.024 80.031 ;
    END
  END addr_in[4]
  PIN addr_in[5]
    DIRECTION INPUT ;
    USE SIGNAL ;
    SHAPE ABUTMENT ;
    PORT
      LAYER M4 ;
      RECT 0.000 80.151 0.024 80.175 ;
    END
  END addr_in[5]
  PIN addr_in[6]
    DIRECTION INPUT ;
    USE SIGNAL ;
    SHAPE ABUTMENT ;
    PORT
      LAYER M4 ;
      RECT 0.000 80.295 0.024 80.319 ;
    END
  END addr_in[6]
  PIN addr_in[7]
    DIRECTION INPUT ;
    USE SIGNAL ;
    SHAPE ABUTMENT ;
    PORT
      LAYER M4 ;
      RECT 0.000 80.439 0.024 80.463 ;
    END
  END addr_in[7]
  PIN we_in
    DIRECTION INPUT ;
    USE SIGNAL ;
    SHAPE ABUTMENT ;
    PORT
      LAYER M4 ;
      RECT 0.000 83.415 0.024 83.439 ;
    END
  END we_in
  PIN ce_in
    DIRECTION INPUT ;
    USE SIGNAL ;
    SHAPE ABUTMENT ;
    PORT
      LAYER M4 ;
      RECT 0.000 83.559 0.024 83.583 ;
    END
  END ce_in
  PIN clk
    DIRECTION INPUT ;
    USE SIGNAL ;
    SHAPE ABUTMENT ;
    PORT
      LAYER M4 ;
      RECT 0.000 83.703 0.024 83.727 ;
    END
  END clk
  PIN VSS
    DIRECTION INOUT ;
    USE GROUND ;
    PORT
      LAYER M4 ;
      RECT 0.048 0.000 33.202 0.096 ;
      RECT 0.048 0.768 33.202 0.864 ;
      RECT 0.048 1.536 33.202 1.632 ;
      RECT 0.048 2.304 33.202 2.400 ;
      RECT 0.048 3.072 33.202 3.168 ;
      RECT 0.048 3.840 33.202 3.936 ;
      RECT 0.048 4.608 33.202 4.704 ;
      RECT 0.048 5.376 33.202 5.472 ;
      RECT 0.048 6.144 33.202 6.240 ;
      RECT 0.048 6.912 33.202 7.008 ;
      RECT 0.048 7.680 33.202 7.776 ;
      RECT 0.048 8.448 33.202 8.544 ;
      RECT 0.048 9.216 33.202 9.312 ;
      RECT 0.048 9.984 33.202 10.080 ;
      RECT 0.048 10.752 33.202 10.848 ;
      RECT 0.048 11.520 33.202 11.616 ;
      RECT 0.048 12.288 33.202 12.384 ;
      RECT 0.048 13.056 33.202 13.152 ;
      RECT 0.048 13.824 33.202 13.920 ;
      RECT 0.048 14.592 33.202 14.688 ;
      RECT 0.048 15.360 33.202 15.456 ;
      RECT 0.048 16.128 33.202 16.224 ;
      RECT 0.048 16.896 33.202 16.992 ;
      RECT 0.048 17.664 33.202 17.760 ;
      RECT 0.048 18.432 33.202 18.528 ;
      RECT 0.048 19.200 33.202 19.296 ;
      RECT 0.048 19.968 33.202 20.064 ;
      RECT 0.048 20.736 33.202 20.832 ;
      RECT 0.048 21.504 33.202 21.600 ;
      RECT 0.048 22.272 33.202 22.368 ;
      RECT 0.048 23.040 33.202 23.136 ;
      RECT 0.048 23.808 33.202 23.904 ;
      RECT 0.048 24.576 33.202 24.672 ;
      RECT 0.048 25.344 33.202 25.440 ;
      RECT 0.048 26.112 33.202 26.208 ;
      RECT 0.048 26.880 33.202 26.976 ;
      RECT 0.048 27.648 33.202 27.744 ;
      RECT 0.048 28.416 33.202 28.512 ;
      RECT 0.048 29.184 33.202 29.280 ;
      RECT 0.048 29.952 33.202 30.048 ;
      RECT 0.048 30.720 33.202 30.816 ;
      RECT 0.048 31.488 33.202 31.584 ;
      RECT 0.048 32.256 33.202 32.352 ;
      RECT 0.048 33.024 33.202 33.120 ;
      RECT 0.048 33.792 33.202 33.888 ;
      RECT 0.048 34.560 33.202 34.656 ;
      RECT 0.048 35.328 33.202 35.424 ;
      RECT 0.048 36.096 33.202 36.192 ;
      RECT 0.048 36.864 33.202 36.960 ;
      RECT 0.048 37.632 33.202 37.728 ;
      RECT 0.048 38.400 33.202 38.496 ;
      RECT 0.048 39.168 33.202 39.264 ;
      RECT 0.048 39.936 33.202 40.032 ;
      RECT 0.048 40.704 33.202 40.800 ;
      RECT 0.048 41.472 33.202 41.568 ;
      RECT 0.048 42.240 33.202 42.336 ;
      RECT 0.048 43.008 33.202 43.104 ;
      RECT 0.048 43.776 33.202 43.872 ;
      RECT 0.048 44.544 33.202 44.640 ;
      RECT 0.048 45.312 33.202 45.408 ;
      RECT 0.048 46.080 33.202 46.176 ;
      RECT 0.048 46.848 33.202 46.944 ;
      RECT 0.048 47.616 33.202 47.712 ;
      RECT 0.048 48.384 33.202 48.480 ;
      RECT 0.048 49.152 33.202 49.248 ;
      RECT 0.048 49.920 33.202 50.016 ;
      RECT 0.048 50.688 33.202 50.784 ;
      RECT 0.048 51.456 33.202 51.552 ;
      RECT 0.048 52.224 33.202 52.320 ;
      RECT 0.048 52.992 33.202 53.088 ;
      RECT 0.048 53.760 33.202 53.856 ;
      RECT 0.048 54.528 33.202 54.624 ;
      RECT 0.048 55.296 33.202 55.392 ;
      RECT 0.048 56.064 33.202 56.160 ;
      RECT 0.048 56.832 33.202 56.928 ;
      RECT 0.048 57.600 33.202 57.696 ;
      RECT 0.048 58.368 33.202 58.464 ;
      RECT 0.048 59.136 33.202 59.232 ;
      RECT 0.048 59.904 33.202 60.000 ;
      RECT 0.048 60.672 33.202 60.768 ;
      RECT 0.048 61.440 33.202 61.536 ;
      RECT 0.048 62.208 33.202 62.304 ;
      RECT 0.048 62.976 33.202 63.072 ;
      RECT 0.048 63.744 33.202 63.840 ;
      RECT 0.048 64.512 33.202 64.608 ;
      RECT 0.048 65.280 33.202 65.376 ;
      RECT 0.048 66.048 33.202 66.144 ;
      RECT 0.048 66.816 33.202 66.912 ;
      RECT 0.048 67.584 33.202 67.680 ;
      RECT 0.048 68.352 33.202 68.448 ;
      RECT 0.048 69.120 33.202 69.216 ;
      RECT 0.048 69.888 33.202 69.984 ;
      RECT 0.048 70.656 33.202 70.752 ;
      RECT 0.048 71.424 33.202 71.520 ;
      RECT 0.048 72.192 33.202 72.288 ;
      RECT 0.048 72.960 33.202 73.056 ;
      RECT 0.048 73.728 33.202 73.824 ;
      RECT 0.048 74.496 33.202 74.592 ;
      RECT 0.048 75.264 33.202 75.360 ;
      RECT 0.048 76.032 33.202 76.128 ;
      RECT 0.048 76.800 33.202 76.896 ;
      RECT 0.048 77.568 33.202 77.664 ;
      RECT 0.048 78.336 33.202 78.432 ;
      RECT 0.048 79.104 33.202 79.200 ;
      RECT 0.048 79.872 33.202 79.968 ;
      RECT 0.048 80.640 33.202 80.736 ;
      RECT 0.048 81.408 33.202 81.504 ;
      RECT 0.048 82.176 33.202 82.272 ;
      RECT 0.048 82.944 33.202 83.040 ;
      RECT 0.048 83.712 33.202 83.808 ;
    END
  END VSS
  PIN VDD
    DIRECTION INOUT ;
    USE POWER ;
    PORT
      LAYER M4 ;
      RECT 0.048 0.384 33.202 0.480 ;
      RECT 0.048 1.152 33.202 1.248 ;
      RECT 0.048 1.920 33.202 2.016 ;
      RECT 0.048 2.688 33.202 2.784 ;
      RECT 0.048 3.456 33.202 3.552 ;
      RECT 0.048 4.224 33.202 4.320 ;
      RECT 0.048 4.992 33.202 5.088 ;
      RECT 0.048 5.760 33.202 5.856 ;
      RECT 0.048 6.528 33.202 6.624 ;
      RECT 0.048 7.296 33.202 7.392 ;
      RECT 0.048 8.064 33.202 8.160 ;
      RECT 0.048 8.832 33.202 8.928 ;
      RECT 0.048 9.600 33.202 9.696 ;
      RECT 0.048 10.368 33.202 10.464 ;
      RECT 0.048 11.136 33.202 11.232 ;
      RECT 0.048 11.904 33.202 12.000 ;
      RECT 0.048 12.672 33.202 12.768 ;
      RECT 0.048 13.440 33.202 13.536 ;
      RECT 0.048 14.208 33.202 14.304 ;
      RECT 0.048 14.976 33.202 15.072 ;
      RECT 0.048 15.744 33.202 15.840 ;
      RECT 0.048 16.512 33.202 16.608 ;
      RECT 0.048 17.280 33.202 17.376 ;
      RECT 0.048 18.048 33.202 18.144 ;
      RECT 0.048 18.816 33.202 18.912 ;
      RECT 0.048 19.584 33.202 19.680 ;
      RECT 0.048 20.352 33.202 20.448 ;
      RECT 0.048 21.120 33.202 21.216 ;
      RECT 0.048 21.888 33.202 21.984 ;
      RECT 0.048 22.656 33.202 22.752 ;
      RECT 0.048 23.424 33.202 23.520 ;
      RECT 0.048 24.192 33.202 24.288 ;
      RECT 0.048 24.960 33.202 25.056 ;
      RECT 0.048 25.728 33.202 25.824 ;
      RECT 0.048 26.496 33.202 26.592 ;
      RECT 0.048 27.264 33.202 27.360 ;
      RECT 0.048 28.032 33.202 28.128 ;
      RECT 0.048 28.800 33.202 28.896 ;
      RECT 0.048 29.568 33.202 29.664 ;
      RECT 0.048 30.336 33.202 30.432 ;
      RECT 0.048 31.104 33.202 31.200 ;
      RECT 0.048 31.872 33.202 31.968 ;
      RECT 0.048 32.640 33.202 32.736 ;
      RECT 0.048 33.408 33.202 33.504 ;
      RECT 0.048 34.176 33.202 34.272 ;
      RECT 0.048 34.944 33.202 35.040 ;
      RECT 0.048 35.712 33.202 35.808 ;
      RECT 0.048 36.480 33.202 36.576 ;
      RECT 0.048 37.248 33.202 37.344 ;
      RECT 0.048 38.016 33.202 38.112 ;
      RECT 0.048 38.784 33.202 38.880 ;
      RECT 0.048 39.552 33.202 39.648 ;
      RECT 0.048 40.320 33.202 40.416 ;
      RECT 0.048 41.088 33.202 41.184 ;
      RECT 0.048 41.856 33.202 41.952 ;
      RECT 0.048 42.624 33.202 42.720 ;
      RECT 0.048 43.392 33.202 43.488 ;
      RECT 0.048 44.160 33.202 44.256 ;
      RECT 0.048 44.928 33.202 45.024 ;
      RECT 0.048 45.696 33.202 45.792 ;
      RECT 0.048 46.464 33.202 46.560 ;
      RECT 0.048 47.232 33.202 47.328 ;
      RECT 0.048 48.000 33.202 48.096 ;
      RECT 0.048 48.768 33.202 48.864 ;
      RECT 0.048 49.536 33.202 49.632 ;
      RECT 0.048 50.304 33.202 50.400 ;
      RECT 0.048 51.072 33.202 51.168 ;
      RECT 0.048 51.840 33.202 51.936 ;
      RECT 0.048 52.608 33.202 52.704 ;
      RECT 0.048 53.376 33.202 53.472 ;
      RECT 0.048 54.144 33.202 54.240 ;
      RECT 0.048 54.912 33.202 55.008 ;
      RECT 0.048 55.680 33.202 55.776 ;
      RECT 0.048 56.448 33.202 56.544 ;
      RECT 0.048 57.216 33.202 57.312 ;
      RECT 0.048 57.984 33.202 58.080 ;
      RECT 0.048 58.752 33.202 58.848 ;
      RECT 0.048 59.520 33.202 59.616 ;
      RECT 0.048 60.288 33.202 60.384 ;
      RECT 0.048 61.056 33.202 61.152 ;
      RECT 0.048 61.824 33.202 61.920 ;
      RECT 0.048 62.592 33.202 62.688 ;
      RECT 0.048 63.360 33.202 63.456 ;
      RECT 0.048 64.128 33.202 64.224 ;
      RECT 0.048 64.896 33.202 64.992 ;
      RECT 0.048 65.664 33.202 65.760 ;
      RECT 0.048 66.432 33.202 66.528 ;
      RECT 0.048 67.200 33.202 67.296 ;
      RECT 0.048 67.968 33.202 68.064 ;
      RECT 0.048 68.736 33.202 68.832 ;
      RECT 0.048 69.504 33.202 69.600 ;
      RECT 0.048 70.272 33.202 70.368 ;
      RECT 0.048 71.040 33.202 71.136 ;
      RECT 0.048 71.808 33.202 71.904 ;
      RECT 0.048 72.576 33.202 72.672 ;
      RECT 0.048 73.344 33.202 73.440 ;
      RECT 0.048 74.112 33.202 74.208 ;
      RECT 0.048 74.880 33.202 74.976 ;
      RECT 0.048 75.648 33.202 75.744 ;
      RECT 0.048 76.416 33.202 76.512 ;
      RECT 0.048 77.184 33.202 77.280 ;
      RECT 0.048 77.952 33.202 78.048 ;
      RECT 0.048 78.720 33.202 78.816 ;
      RECT 0.048 79.488 33.202 79.584 ;
      RECT 0.048 80.256 33.202 80.352 ;
      RECT 0.048 81.024 33.202 81.120 ;
      RECT 0.048 81.792 33.202 81.888 ;
      RECT 0.048 82.560 33.202 82.656 ;
      RECT 0.048 83.328 33.202 83.424 ;
    END
  END VDD
  OBS
    LAYER M1 ;
    RECT 0 0 33.250 84.000 ;
    LAYER M2 ;
    RECT 0 0 33.250 84.000 ;
    LAYER M3 ;
    RECT 0.059 0.000 33.250 84.000 ;
    LAYER M4 ;
    RECT 0.059 0.000 33.250 84.000 ;
  END
END fakeram7_256x256_bottom

END LIBRARY
